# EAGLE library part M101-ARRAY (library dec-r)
M101 Bus Data Interface

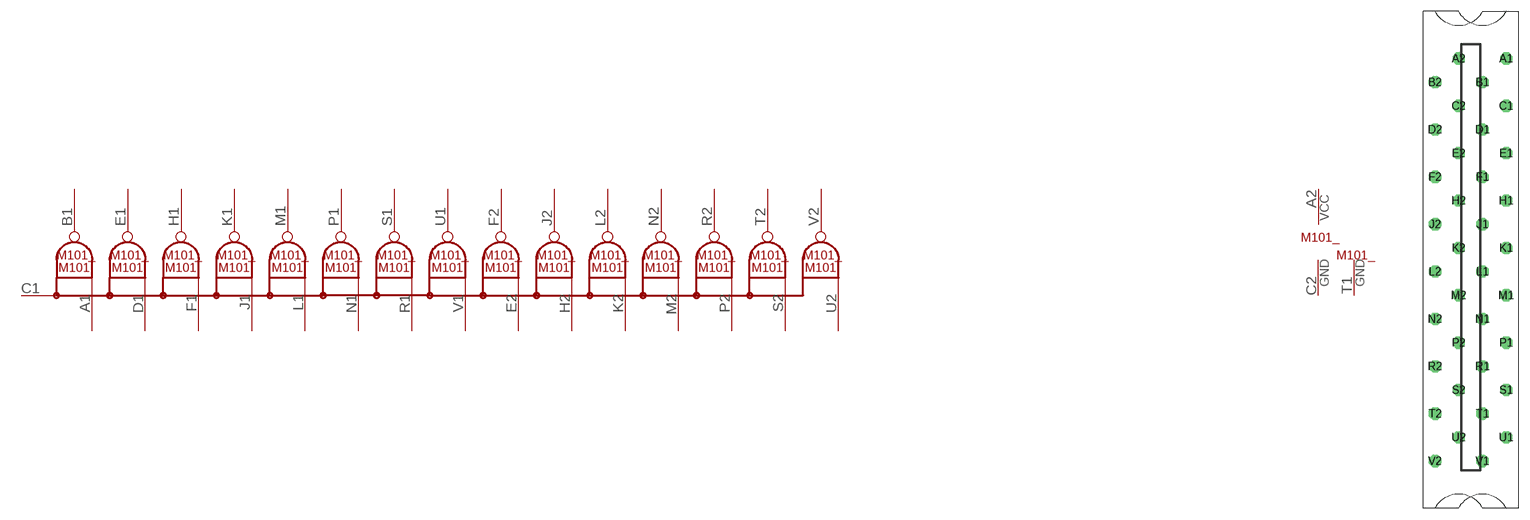
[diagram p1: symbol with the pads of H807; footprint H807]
Designator prefix M101_; gates G$1=M101A G$2=POWER G$3=T1GND

## M101-ARRAY  [H807]
A1  G$1:IN1  in
A2  G$2:VCC  pwr
B1  G$1:O1  out
C1  G$1:ENABLE  in
C2  G$2:GND  pwr
D1  G$1:IN2  in
E1  G$1:O2  out
E2  G$1:IN9  in
F1  G$1:IN3  in
F2  G$1:O9  out
H1  G$1:O3  out
H2  G$1:IN10  in
J1  G$1:IN4  in
J2  G$1:O10  out
K1  G$1:O4  out
K2  G$1:IN11  in
L1  G$1:IN5  in
L2  G$1:O11  out
M1  G$1:O5  out
M2  G$1:IN12  in
N1  G$1:IN6  in
N2  G$1:O12  out
P1  G$1:O6  out
P2  G$1:IN13  in
R1  G$1:IN7  in
R2  G$1:O13  out
S1  G$1:O7  out
S2  G$1:IN14  in
T1  G$3:GND  pwr
T2  G$1:O14  out
U1  G$1:O8  out
U2  G$1:IN15  in
V1  G$1:IN8  in
V2  G$1:O15  out

## Footprint H807 (pad centres in mm)
One-wide female edge connector
drill 1.092 octagon: A1 4.763,28.575; A2 -1.587,28.575; B1 1.587,25.4; B2 -4.763,25.4; C1 4.763,22.225; C2 -1.587,22.225; D1 1.587,19.05; D2 -4.763,19.05; E1 4.763,15.875; E2 -1.587,15.875; F1 1.587,12.7; F2 -4.763,12.7; H1 4.763,9.525; H2 -1.587,9.525; J1 1.587,6.35; J2 -4.763,6.35; K1 4.763,3.175; K2 -1.587,3.175; L1 1.587,0; L2 -4.763,0; M1 4.763,-3.175; M2 -1.587,-3.175; N1 1.587,-6.35; N2 -4.763,-6.35; P1 4.763,-9.525; P2 -1.587,-9.525; R1 1.587,-12.7; R2 -4.763,-12.7; S1 4.763,-15.875; S2 -1.587,-15.875; T1 1.587,-19.05; T2 -4.763,-19.05; U1 4.763,-22.225; U2 -1.587,-22.225; V1 1.587,-25.4; V2 -4.763,-25.4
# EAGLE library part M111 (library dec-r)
Sixteen inverters.

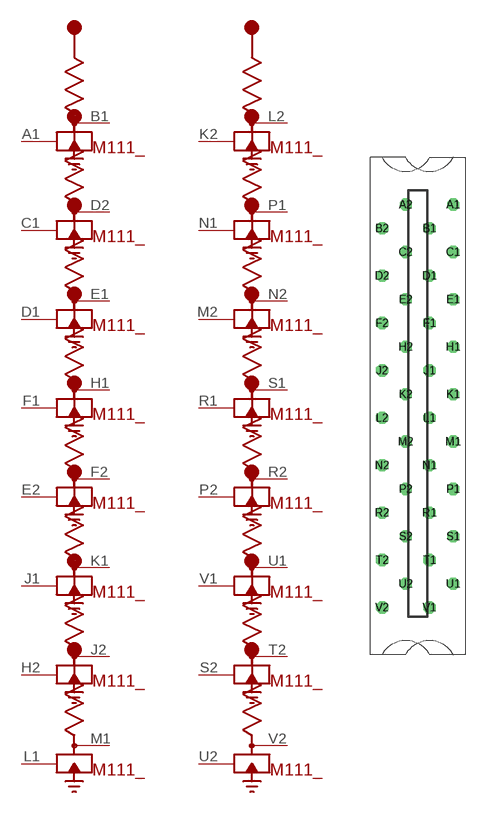
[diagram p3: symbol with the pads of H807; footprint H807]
Designator prefix M111_; gates 3=INVERTER 2=INVERTER 1=INVERTER 13=INVERTER 4=INVERTER 15=INVERTER 14=INVERTER 16=INVERTER 5=INVERTER 6=INVERTER 7=INVERTER 8=INVERTER 9=INVERTER 10=INVERTER 11=INVERTER 12=INVERTER G$17=POWER G$1=T1GND

## M111  [H807]
A1  1:IN  in
A2  G$17:VCC  pwr
B1  1:OUT  out
C1  2:IN  in
C2  G$17:GND  pwr
D1  3:IN  in
D2  2:OUT  out
E1  3:OUT  out
E2  5:IN  in
F1  4:IN  in
F2  5:OUT  out
H1  4:OUT  out
H2  7:IN  in
J1  6:IN  in
J2  7:OUT  out
K1  6:OUT  out
K2  9:IN  in
L1  8:IN  in
L2  9:OUT  out
M1  8:OUT  out
M2  11:IN  in
N1  10:IN  in
N2  11:OUT  out
P1  10:OUT  out
P2  13:IN  in
R1  12:IN  in
R2  13:OUT  out
S1  12:OUT  out
S2  15:IN  in
T1  G$1:GND  pwr
T2  15:OUT  out
U1  14:OUT  out
U2  16:IN  in
V1  14:IN  in
V2  16:OUT  out

## Footprint H807 (pad centres in mm)
One-wide female edge connector
drill 1.092 octagon: A1 4.763,28.575; A2 -1.587,28.575; B1 1.587,25.4; B2 -4.763,25.4; C1 4.763,22.225; C2 -1.587,22.225; D1 1.587,19.05; D2 -4.763,19.05; E1 4.763,15.875; E2 -1.587,15.875; F1 1.587,12.7; F2 -4.763,12.7; H1 4.763,9.525; H2 -1.587,9.525; J1 1.587,6.35; J2 -4.763,6.35; K1 4.763,3.175; K2 -1.587,3.175; L1 1.587,0; L2 -4.763,0; M1 4.763,-3.175; M2 -1.587,-3.175; N1 1.587,-6.35; N2 -4.763,-6.35; P1 4.763,-9.525; P2 -1.587,-9.525; R1 1.587,-12.7; R2 -4.763,-12.7; S1 4.763,-15.875; S2 -1.587,-15.875; T1 1.587,-19.05; T2 -4.763,-19.05; U1 4.763,-22.225; U2 -1.587,-22.225; V1 1.587,-25.4; V2 -4.763,-25.4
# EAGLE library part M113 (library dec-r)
10 2-input NAND Gates

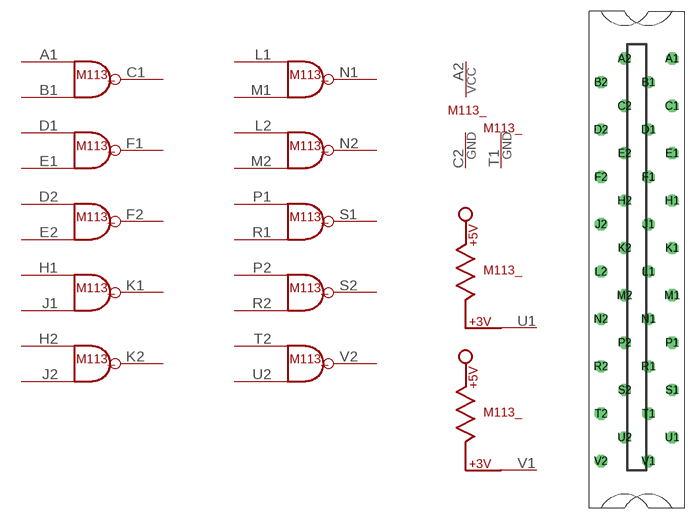
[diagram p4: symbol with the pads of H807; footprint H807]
Designator prefix M113_; gates G$1=NAND2 G$2=NAND2 G$3=NAND2 G$4=NAND2 G$5=NAND2 G$6=NAND2 G$7=NAND2 G$8=NAND2 G$9=NAND2 G$10=NAND2 G$11=POWER G$12=T1GND G$13=PULL-UP G$14=PULL-UP

## M113  [H807]
A1  G$1:IN1  in
A2  G$11:VCC  pwr
B1  G$1:IN2  in
C1  G$1:OUT  out
C2  G$11:GND  pwr
D1  G$2:IN1  in
D2  G$3:IN1  in
E1  G$2:IN2  in
E2  G$3:IN2  in
F1  G$2:OUT  out
F2  G$3:OUT  out
H1  G$4:IN1  in
H2  G$5:IN1  in
J1  G$4:IN2  in
J2  G$5:IN2  in
K1  G$4:OUT  out
K2  G$5:OUT  out
L1  G$6:IN1  in
L2  G$7:IN1  in
M1  G$6:IN2  in
M2  G$7:IN2  in
N1  G$6:OUT  out
N2  G$7:OUT  out
P1  G$8:IN1  in
P2  G$9:IN1  in
R1  G$8:IN2  in
R2  G$9:IN2  in
S1  G$8:OUT  out
S2  G$9:OUT  out
T1  G$12:GND  pwr
T2  G$10:IN1  in
U1  G$13:P$1  pas
U2  G$10:IN2  in
V1  G$14:P$1  pas
V2  G$10:OUT  out

## Footprint H807 (pad centres in mm)
One-wide female edge connector
drill 1.092 octagon: A1 4.763,28.575; A2 -1.587,28.575; B1 1.587,25.4; B2 -4.763,25.4; C1 4.763,22.225; C2 -1.587,22.225; D1 1.587,19.05; D2 -4.763,19.05; E1 4.763,15.875; E2 -1.587,15.875; F1 1.587,12.7; F2 -4.763,12.7; H1 4.763,9.525; H2 -1.587,9.525; J1 1.587,6.35; J2 -4.763,6.35; K1 4.763,3.175; K2 -1.587,3.175; L1 1.587,0; L2 -4.763,0; M1 4.763,-3.175; M2 -1.587,-3.175; N1 1.587,-6.35; N2 -4.763,-6.35; P1 4.763,-9.525; P2 -1.587,-9.525; R1 1.587,-12.7; R2 -4.763,-12.7; S1 4.763,-15.875; S2 -1.587,-15.875; T1 1.587,-19.05; T2 -4.763,-19.05; U1 4.763,-22.225; U2 -1.587,-22.225; V1 1.587,-25.4; V2 -4.763,-25.4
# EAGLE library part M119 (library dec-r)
3 8-input NAND Gates

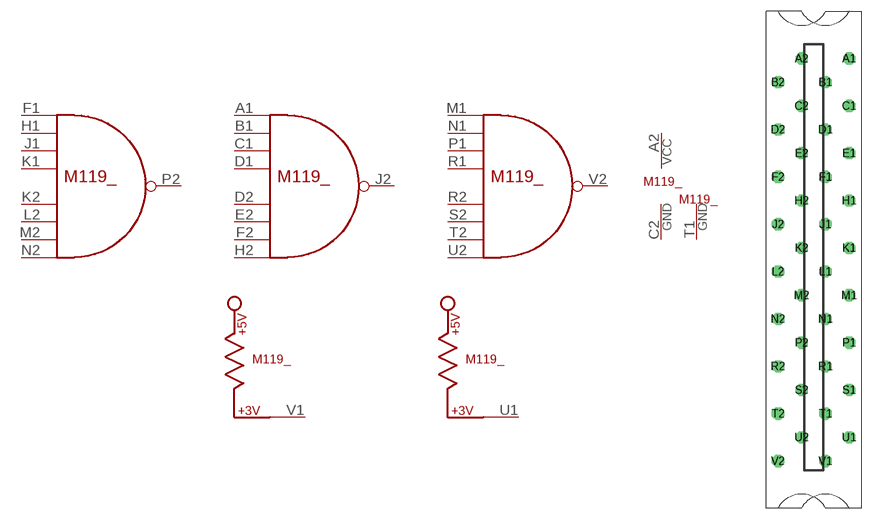
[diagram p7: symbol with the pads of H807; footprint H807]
Designator prefix M119_; gates G$1=NAND8 G$2=NAND8 G$3=NAND8 G$4=POWER G$5=T1GND G$6=PULL-UP G$7=PULL-UP

## M119  [H807]
A1  G$1:IN1  in
A2  G$4:VCC  pwr
B1  G$1:IN2  in
C1  G$1:IN3  in
C2  G$4:GND  pwr
D1  G$1:IN4  in
D2  G$1:IN5  in
E2  G$1:IN6  in
F1  G$2:IN1  in
F2  G$1:IN7  in
H1  G$2:IN2  in
H2  G$1:IN8  in
J1  G$2:IN3  in
J2  G$1:OUT  out
K1  G$2:IN4  in
K2  G$2:IN5  in
L2  G$2:IN6  in
M1  G$3:IN1  in
M2  G$2:IN7  in
N1  G$3:IN2  in
N2  G$2:IN8  in
P1  G$3:IN3  in
P2  G$2:OUT  out
R1  G$3:IN4  in
R2  G$3:IN5  in
S2  G$3:IN6  in
T1  G$5:GND  pwr
T2  G$3:IN7  in
U1  G$6:P$1  pas
U2  G$3:IN8  in
V1  G$7:P$1  pas
V2  G$3:OUT  out

## Footprint H807 (pad centres in mm)
One-wide female edge connector
drill 1.092 octagon: A1 4.763,28.575; A2 -1.587,28.575; B1 1.587,25.4; B2 -4.763,25.4; C1 4.763,22.225; C2 -1.587,22.225; D1 1.587,19.05; D2 -4.763,19.05; E1 4.763,15.875; E2 -1.587,15.875; F1 1.587,12.7; F2 -4.763,12.7; H1 4.763,9.525; H2 -1.587,9.525; J1 1.587,6.35; J2 -4.763,6.35; K1 4.763,3.175; K2 -1.587,3.175; L1 1.587,0; L2 -4.763,0; M1 4.763,-3.175; M2 -1.587,-3.175; N1 1.587,-6.35; N2 -4.763,-6.35; P1 4.763,-9.525; P2 -1.587,-9.525; R1 1.587,-12.7; R2 -4.763,-12.7; S1 4.763,-15.875; S2 -1.587,-15.875; T1 1.587,-19.05; T2 -4.763,-19.05; U1 4.763,-22.225; U2 -1.587,-22.225; V1 1.587,-25.4; V2 -4.763,-25.4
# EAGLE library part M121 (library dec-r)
6 2-2 AND-NOR Gates

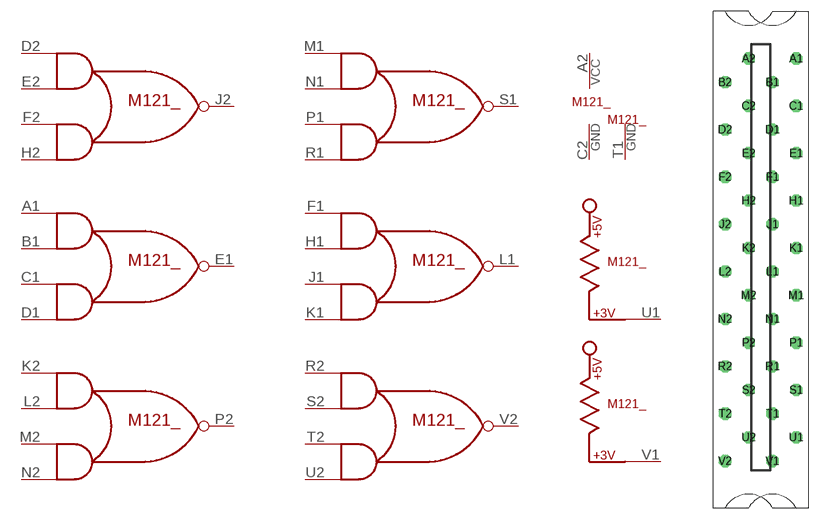
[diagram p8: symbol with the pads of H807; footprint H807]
Designator prefix M121_; gates G$1=AND-NOR G$2=AND-NOR G$3=AND-NOR G$4=AND-NOR G$5=AND-NOR G$6=AND-NOR G$7=POWER G$8=T1GND G$9=PULL-UP G$10=PULL-UP

## M121  [H807]
A1  G$1:IN1A  in
A2  G$7:VCC  pwr
B1  G$1:IN1B  in
C1  G$1:IN2A  in
C2  G$7:GND  pwr
D1  G$1:IN2B  in
D2  G$4:IN1A  in
E1  G$1:OUT  out
E2  G$4:IN1B  in
F1  G$2:IN1A  in
F2  G$4:IN2A  in
H1  G$2:IN1B  in
H2  G$4:IN2B  in
J1  G$2:IN2A  in
J2  G$4:OUT  out
K1  G$2:IN2B  in
K2  G$5:IN1A  in
L1  G$2:OUT  out
L2  G$5:IN1B  in
M1  G$3:IN1A  in
M2  G$5:IN2A  in
N1  G$3:IN1B  in
N2  G$5:IN2B  in
P1  G$3:IN2A  in
P2  G$5:OUT  out
R1  G$3:IN2B  in
R2  G$6:IN1A  in
S1  G$3:OUT  out
S2  G$6:IN1B  in
T1  G$8:GND  pwr
T2  G$6:IN2A  in
U1  G$9:P$1  pas
U2  G$6:IN2B  in
V1  G$10:P$1  pas
V2  G$6:OUT  out

## Footprint H807 (pad centres in mm)
One-wide female edge connector
drill 1.092 octagon: A1 4.763,28.575; A2 -1.587,28.575; B1 1.587,25.4; B2 -4.763,25.4; C1 4.763,22.225; C2 -1.587,22.225; D1 1.587,19.05; D2 -4.763,19.05; E1 4.763,15.875; E2 -1.587,15.875; F1 1.587,12.7; F2 -4.763,12.7; H1 4.763,9.525; H2 -1.587,9.525; J1 1.587,6.35; J2 -4.763,6.35; K1 4.763,3.175; K2 -1.587,3.175; L1 1.587,0; L2 -4.763,0; M1 4.763,-3.175; M2 -1.587,-3.175; N1 1.587,-6.35; N2 -4.763,-6.35; P1 4.763,-9.525; P2 -1.587,-9.525; R1 1.587,-12.7; R2 -4.763,-12.7; S1 4.763,-15.875; S2 -1.587,-15.875; T1 1.587,-19.05; T2 -4.763,-19.05; U1 4.763,-22.225; U2 -1.587,-22.225; V1 1.587,-25.4; V2 -4.763,-25.4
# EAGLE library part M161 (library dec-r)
Octal or Decimal Decoder

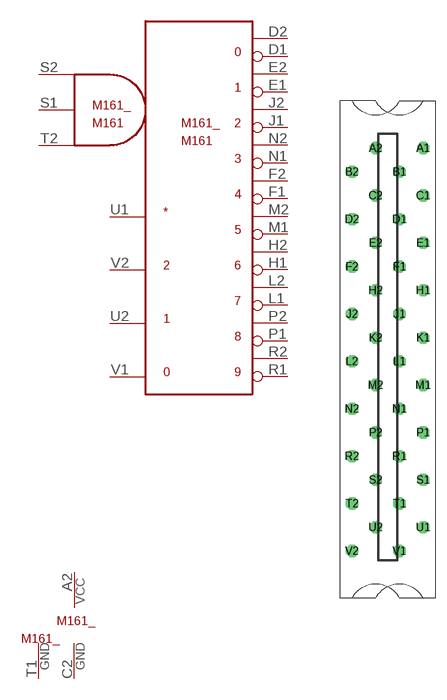
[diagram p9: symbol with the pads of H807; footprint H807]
Designator prefix M161_; gates G$1=M161 G$2=POWER G$3=T1GND

## M161  [H807]
A2  G$2:VCC  pwr
C2  G$2:GND  pwr
D1  G$1:O0\  out
D2  G$1:O0  out
E1  G$1:O1\  out
E2  G$1:O1  out
F1  G$1:O4\  out
F2  G$1:O4  out
H1  G$1:O6\  out
H2  G$1:O6  out
J1  G$1:O2\  out
J2  G$1:O2  out
L1  G$1:O7\  out
L2  G$1:O7  out
M1  G$1:O5\  out
M2  G$1:O5  out
N1  G$1:O3\  out
N2  G$1:O3  out
P1  G$1:O8\  out
P2  G$1:O8  out
R1  G$1:O9\  out
R2  G$1:O9  out
S1  G$1:EN2  in
S2  G$1:EN1  in
T1  G$3:GND  pwr
T2  G$1:EN3  in
U1  G$1:IN*  in
U2  G$1:IN1  in
V1  G$1:IN0  in
V2  G$1:IN2  in

## Footprint H807 (pad centres in mm)
One-wide female edge connector
drill 1.092 octagon: A1 4.763,28.575; A2 -1.587,28.575; B1 1.587,25.4; B2 -4.763,25.4; C1 4.763,22.225; C2 -1.587,22.225; D1 1.587,19.05; D2 -4.763,19.05; E1 4.763,15.875; E2 -1.587,15.875; F1 1.587,12.7; F2 -4.763,12.7; H1 4.763,9.525; H2 -1.587,9.525; J1 1.587,6.35; J2 -4.763,6.35; K1 4.763,3.175; K2 -1.587,3.175; L1 1.587,0; L2 -4.763,0; M1 4.763,-3.175; M2 -1.587,-3.175; N1 1.587,-6.35; N2 -4.763,-6.35; P1 4.763,-9.525; P2 -1.587,-9.525; R1 1.587,-12.7; R2 -4.763,-12.7; S1 4.763,-15.875; S2 -1.587,-15.875; T1 1.587,-19.05; T2 -4.763,-19.05; U1 4.763,-22.225; U2 -1.587,-22.225; V1 1.587,-25.4; V2 -4.763,-25.4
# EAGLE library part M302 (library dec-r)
Dual one-shot

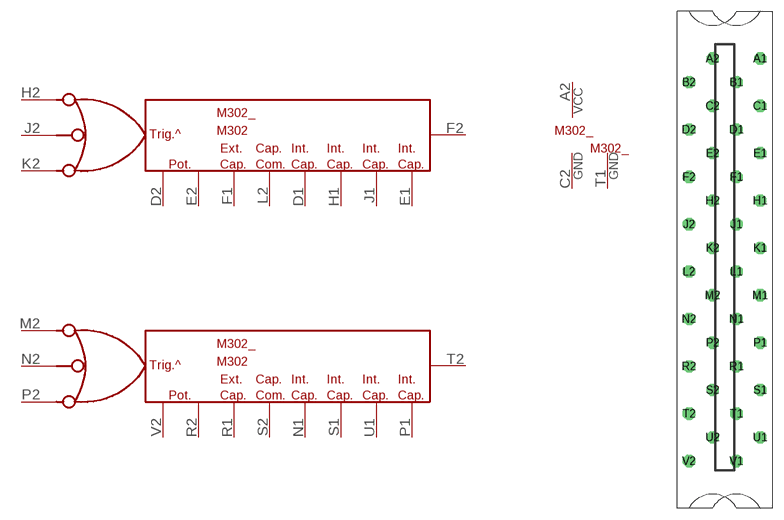
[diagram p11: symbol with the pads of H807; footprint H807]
Designator prefix M302_; gates G$1=M302A G$2=M302A G$3=POWER G$4=T1GND

## M302  [H807]
A2  G$3:VCC  pwr
C2  G$3:GND  pwr
D1  G$1:D1  pas
D2  G$1:D2  pas
E1  G$1:E1  pas
E2  G$1:E2  pas
F1  G$1:F1  pas
F2  G$1:F2  out
H1  G$1:H1  pas
H2  G$1:H2  in
J1  G$1:J1  pas
J2  G$1:J2  in
K2  G$1:K2  in
L2  G$1:L2  pas
M2  G$2:H2  in
N1  G$2:D1  pas
N2  G$2:J2  in
P1  G$2:E1  pas
P2  G$2:K2  in
R1  G$2:F1  pas
R2  G$2:E2  pas
S1  G$2:H1  pas
S2  G$2:L2  pas
T1  G$4:GND  pwr
T2  G$2:F2  out
U1  G$2:J1  pas
V2  G$2:D2  pas

## Footprint H807 (pad centres in mm)
One-wide female edge connector
drill 1.092 octagon: A1 4.763,28.575; A2 -1.587,28.575; B1 1.587,25.4; B2 -4.763,25.4; C1 4.763,22.225; C2 -1.587,22.225; D1 1.587,19.05; D2 -4.763,19.05; E1 4.763,15.875; E2 -1.587,15.875; F1 1.587,12.7; F2 -4.763,12.7; H1 4.763,9.525; H2 -1.587,9.525; J1 1.587,6.35; J2 -4.763,6.35; K1 4.763,3.175; K2 -1.587,3.175; L1 1.587,0; L2 -4.763,0; M1 4.763,-3.175; M2 -1.587,-3.175; N1 1.587,-6.35; N2 -4.763,-6.35; P1 4.763,-9.525; P2 -1.587,-9.525; R1 1.587,-12.7; R2 -4.763,-12.7; S1 4.763,-15.875; S2 -1.587,-15.875; T1 1.587,-19.05; T2 -4.763,-19.05; U1 4.763,-22.225; U2 -1.587,-22.225; V1 1.587,-25.4; V2 -4.763,-25.4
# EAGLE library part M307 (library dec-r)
Dual Integrating One-Shot

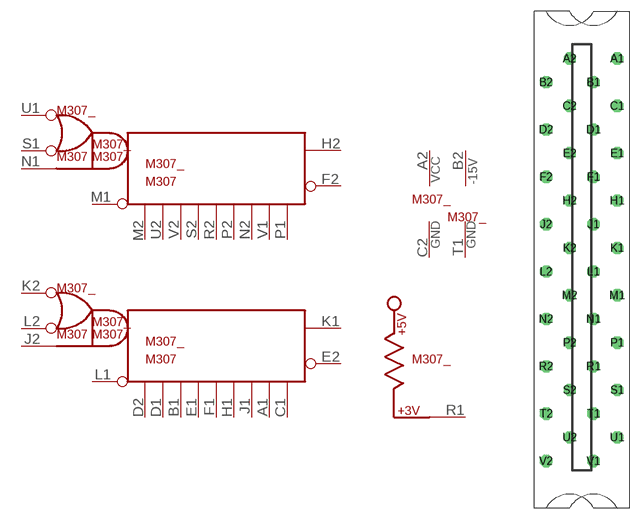
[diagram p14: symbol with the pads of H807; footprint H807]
Designator prefix M307_; gates G$1=M307A G$2=M307A G$3=POWER G$4=T1GND G$5=-15V G$6=PULL-UP

## M307  [H807]
A1  G$2:V1  pas
A2  G$3:VCC  pwr
B1  G$2:V2  pas
B2  G$5:-15V  pwr
C1  G$2:P1  pas
C2  G$3:GND  pwr
D1  G$2:U2  pas
D2  G$2:M2  pas
E1  G$2:S2  pas
E2  G$2:F2  out
F1  G$2:R2  pas
F2  G$1:F2  out
H1  G$2:P2  pas
H2  G$1:H2  out
J1  G$2:N2  pas
J2  G$2:N1  in
K1  G$2:H2  out
K2  G$2:U1  in
L1  G$2:M1  in
L2  G$2:S1  in
M1  G$1:M1  in
M2  G$1:M2  pas
N1  G$1:N1  in
N2  G$1:N2  pas
P1  G$1:P1  pas
P2  G$1:P2  pas
R1  G$6:P$1  pas
R2  G$1:R2  pas
S1  G$1:S1  in
S2  G$1:S2  pas
T1  G$4:GND  pwr
U1  G$1:U1  in
U2  G$1:U2  pas
V1  G$1:V1  pas
V2  G$1:V2  pas

## Footprint H807 (pad centres in mm)
One-wide female edge connector
drill 1.092 octagon: A1 4.763,28.575; A2 -1.587,28.575; B1 1.587,25.4; B2 -4.763,25.4; C1 4.763,22.225; C2 -1.587,22.225; D1 1.587,19.05; D2 -4.763,19.05; E1 4.763,15.875; E2 -1.587,15.875; F1 1.587,12.7; F2 -4.763,12.7; H1 4.763,9.525; H2 -1.587,9.525; J1 1.587,6.35; J2 -4.763,6.35; K1 4.763,3.175; K2 -1.587,3.175; L1 1.587,0; L2 -4.763,0; M1 4.763,-3.175; M2 -1.587,-3.175; N1 1.587,-6.35; N2 -4.763,-6.35; P1 4.763,-9.525; P2 -1.587,-9.525; R1 1.587,-12.7; R2 -4.763,-12.7; S1 4.763,-15.875; S2 -1.587,-15.875; T1 1.587,-19.05; T2 -4.763,-19.05; U1 4.763,-22.225; U2 -1.587,-22.225; V1 1.587,-25.4; V2 -4.763,-25.4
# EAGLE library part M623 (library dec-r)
6 Dual Bus Drivers

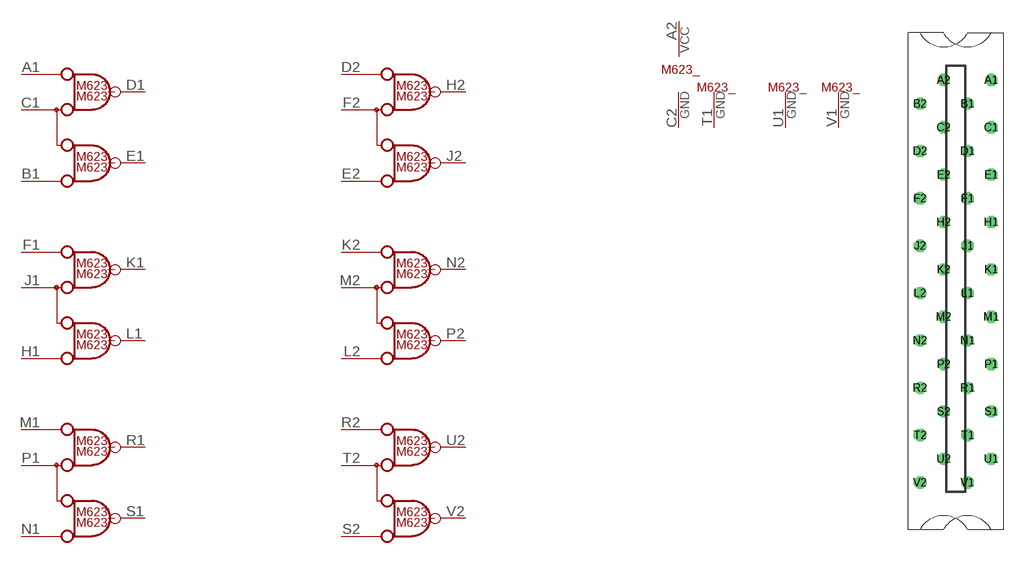
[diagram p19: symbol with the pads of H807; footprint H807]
Designator prefix M623_; gates G$1=M623A G$2=M623A G$3=M623A G$4=M623A G$5=M623A G$6=M623A G$7=POWER G$8=T1GND G$9=T1GND G$10=T1GND

## M623  [H807]
A1  G$1:A  in
A2  G$7:VCC  pwr
B1  G$1:B  in
C1  G$1:C  in
C2  G$7:GND  pwr
D1  G$1:D  oc
D2  G$4:A  in
E1  G$1:E  oc
E2  G$4:B  in
F1  G$2:A  in
F2  G$4:C  in
H1  G$2:B  in
H2  G$4:D  oc
J1  G$2:C  in
J2  G$4:E  oc
K1  G$2:D  oc
K2  G$5:A  in
L1  G$2:E  oc
L2  G$5:B  in
M1  G$3:A  in
M2  G$5:C  in
N1  G$3:B  in
N2  G$5:D  oc
P1  G$3:C  in
P2  G$5:E  oc
R1  G$3:D  oc
R2  G$6:A  in
S1  G$3:E  oc
S2  G$6:B  in
T1  G$8:GND  pwr
T2  G$6:C  in
U1  G$9:GND  pwr
U2  G$6:D  oc
V1  G$10:GND  pwr
V2  G$6:E  oc

## Footprint H807 (pad centres in mm)
One-wide female edge connector
drill 1.092 octagon: A1 4.763,28.575; A2 -1.587,28.575; B1 1.587,25.4; B2 -4.763,25.4; C1 4.763,22.225; C2 -1.587,22.225; D1 1.587,19.05; D2 -4.763,19.05; E1 4.763,15.875; E2 -1.587,15.875; F1 1.587,12.7; F2 -4.763,12.7; H1 4.763,9.525; H2 -1.587,9.525; J1 1.587,6.35; J2 -4.763,6.35; K1 4.763,3.175; K2 -1.587,3.175; L1 1.587,0; L2 -4.763,0; M1 4.763,-3.175; M2 -1.587,-3.175; N1 1.587,-6.35; N2 -4.763,-6.35; P1 4.763,-9.525; P2 -1.587,-9.525; R1 1.587,-12.7; R2 -4.763,-12.7; S1 4.763,-15.875; S2 -1.587,-15.875; T1 1.587,-19.05; T2 -4.763,-19.05; U1 4.763,-22.225; U2 -1.587,-22.225; V1 1.587,-25.4; V2 -4.763,-25.4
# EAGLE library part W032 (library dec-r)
Cable Connector (15 signals)

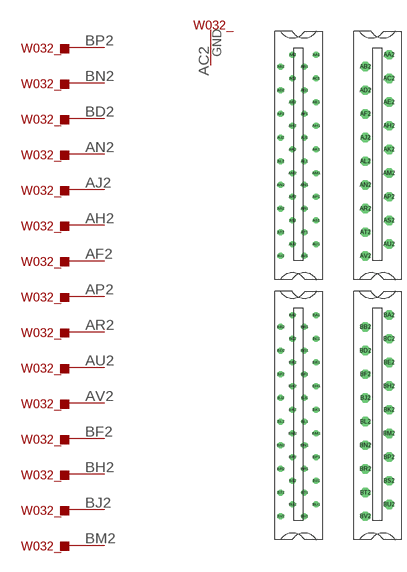
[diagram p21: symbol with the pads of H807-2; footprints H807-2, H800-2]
Designator prefix W032_; gates AF=PIN AH=PIN AJ=PIN AN=PIN AP=PIN AR=PIN AU=PIN AV=PIN BD=PIN BF=PIN BH=PIN BJ=PIN BM=PIN BN=PIN BP=PIN G$16=T1GND G$17=T1GND G$18=T1GND G$19=T1GND G$20=T1GND G$21=T1GND

## W032  [H807-2]
AC2  G$16:GND  pwr
AF2  AF:P$2
AH2  AH:P$2
AJ2  AJ:P$2
AK2  G$17:GND  pwr
AN2  AN:P$2
AP2  AP:P$2
AR2  AR:P$2
AS2  G$18:GND  pwr
AT2  G$19:GND  pwr
AU2  AU:P$2
AV2  AV:P$2
BD2  BD:P$2
BE2  G$20:GND  pwr
BF2  BF:P$2
BH2  BH:P$2
BJ2  BJ:P$2
BL2  G$21:GND  pwr
BM2  BM:P$2
BN2  BN:P$2
BP2  BP:P$2

## W032O  [H800-2]
Pads as for H807-2

## W032S  [H807S-2]
Pads as for H807-2

## Footprint H807-2 (pad centres in mm)
Two-wide Female Edge Connector
drill 1.092 octagon: AA1 4.763,60.325; AA2 -1.587,60.325; AB1 1.587,57.15; AB2 -4.763,57.15; AC1 4.763,53.975; AC2 -1.587,53.975; AD1 1.587,50.8; AD2 -4.763,50.8; AE1 4.763,47.625; AE2 -1.587,47.625; AF1 1.587,44.45; AF2 -4.763,44.45; AH1 4.763,41.275; AH2 -1.587,41.275; AJ1 1.587,38.1; AJ2 -4.763,38.1; AK1 4.763,34.925; AK2 -1.587,34.925; AL1 1.587,31.75; AL2 -4.763,31.75; AM1 4.763,28.575; AM2 -1.587,28.575; AN1 1.587,25.4; AN2 -4.763,25.4; AP1 4.763,22.225; AP2 -1.587,22.225; AR1 1.587,19.05; AR2 -4.763,19.05; AS1 4.763,15.875; AS2 -1.587,15.875; AT1 1.587,12.7; AT2 -4.763,12.7; AU1 4.763,9.525; AU2 -1.587,9.525; AV1 1.587,6.35; AV2 -4.763,6.35; BA1 4.763,-9.525; BA2 -1.587,-9.525; BB1 1.587,-12.7; BB2 -4.763,-12.7; BC1 4.763,-15.875; BC2 -1.587,-15.875; BD1 1.587,-19.05; BD2 -4.763,-19.05; BE1 4.763,-22.225; BE2 -1.587,-22.225; BF1 1.587,-25.4; BF2 -4.763,-25.4; BH1 4.763,-28.575; BH2 -1.587,-28.575; BJ1 1.587,-31.75; BJ2 -4.763,-31.75; BK1 4.763,-34.925; BK2 -1.587,-34.925; BL1 1.587,-38.1; BL2 -4.763,-38.1; BM1 4.763,-41.275; BM2 -1.587,-41.275; BN1 1.587,-44.45; BN2 -4.763,-44.45; BP1 4.763,-47.625; BP2 -1.587,-47.625; BR1 1.587,-50.8; BR2 -4.763,-50.8; BS1 4.763,-53.975; BS2 -1.587,-53.975; BT1 1.587,-57.15; BT2 -4.763,-57.15; BU1 4.763,-60.325; BU2 -1.587,-60.325; BV1 1.587,-63.5; BV2 -4.763,-63.5

## Footprint H800-2 (pad centres in mm)
Two-wide Female Edge Connector
drill 1.676 octagon: AA2 3.175,60.325; AB2 -3.175,57.15; AC2 3.175,53.975; AD2 -3.175,50.8; AE2 3.175,47.625; AF2 -3.175,44.45; AH2 3.175,41.275; AJ2 -3.175,38.1; AK2 3.175,34.925; AL2 -3.175,31.75; AM2 3.175,28.575; AN2 -3.175,25.4; AP2 3.175,22.225; AR2 -3.175,19.05; AS2 3.175,15.875; AT2 -3.175,12.7; AU2 3.175,9.525; AV2 -3.175,6.35; BA2 3.175,-9.525; BB2 -3.175,-12.7; BC2 3.175,-15.875; BD2 -3.175,-19.05; BE2 3.175,-22.225; BF2 -3.175,-25.4; BH2 3.175,-28.575; BJ2 -3.175,-31.75; BK2 3.175,-34.925; BL2 -3.175,-38.1; BM2 3.175,-41.275; BN2 -3.175,-44.45; BP2 3.175,-47.625; BR2 -3.175,-50.8; BS2 3.175,-53.975; BT2 -3.175,-57.15; BU2 3.175,-60.325; BV2 -3.175,-63.5

## Footprint H807S-2 (pad centres in mm)
Two-wide Female Edge Connector, Side 2 only
drill 1.092 octagon: AA2 -1.587,60.325; AB2 -4.763,57.15; AC2 -1.587,53.975; AD2 -4.763,50.8; AE2 -1.587,47.625; AF2 -4.763,44.45; AH2 -1.587,41.275; AJ2 -4.763,38.1; AK2 -1.587,34.925; AL2 -4.763,31.75; AM2 -1.587,28.575; AN2 -4.763,25.4; AP2 -1.587,22.225; AR2 -4.763,19.05; AS2 -1.587,15.875; AT2 -4.763,12.7; AU2 -1.587,9.525; AV2 -4.763,6.35; BA2 -1.587,-9.525; BB2 -4.763,-12.7; BC2 -1.587,-15.875; BD2 -4.763,-19.05; BE2 -1.587,-22.225; BF2 -4.763,-25.4; BH2 -1.587,-28.575; BJ2 -4.763,-31.75; BK2 -1.587,-34.925; BL2 -4.763,-38.1; BM2 -1.587,-41.275; BN2 -4.763,-44.45; BP2 -1.587,-47.625; BR2 -4.763,-50.8; BS2 -1.587,-53.975; BT2 -4.763,-57.15; BU2 -1.587,-60.325; BV2 -4.763,-63.5
hole 1.092 at 4.763,60.325
hole 1.092 at 1.587,57.15
hole 1.092 at 4.763,53.975
hole 1.092 at 1.587,50.8
hole 1.092 at 4.763,47.625
hole 1.092 at 1.587,44.45
hole 1.092 at 4.763,41.275
hole 1.092 at 1.587,38.1
hole 1.092 at 4.763,34.925
hole 1.092 at 1.587,31.75
hole 1.092 at 4.763,28.575
hole 1.092 at 4.763,-9.525
hole 1.092 at 1.587,-12.7
hole 1.092 at 4.763,-15.875
hole 1.092 at 1.587,-19.05
hole 1.092 at 4.763,-22.225
hole 1.092 at 1.587,-25.4
hole 1.092 at 4.763,-28.575
hole 1.092 at 1.587,-31.75
hole 1.092 at 4.763,-34.925
hole 1.092 at 1.587,-38.1
hole 1.092 at 4.763,-41.275
hole 1.092 at 1.587,-44.45
hole 1.092 at 4.763,-47.625
hole 1.092 at 1.587,-50.8
hole 1.092 at 4.763,-53.975
hole 1.092 at 1.587,-57.15
hole 1.092 at 4.763,-60.325
hole 1.092 at 1.587,-63.5
hole 1.092 at 1.587,25.4
hole 1.092 at 4.763,22.225
hole 1.092 at 1.587,19.05
hole 1.092 at 4.763,15.875
hole 1.092 at 1.587,12.7
hole 1.092 at 4.763,9.525
hole 1.092 at 1.587,6.35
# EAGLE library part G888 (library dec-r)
Manchester Reader/Writer

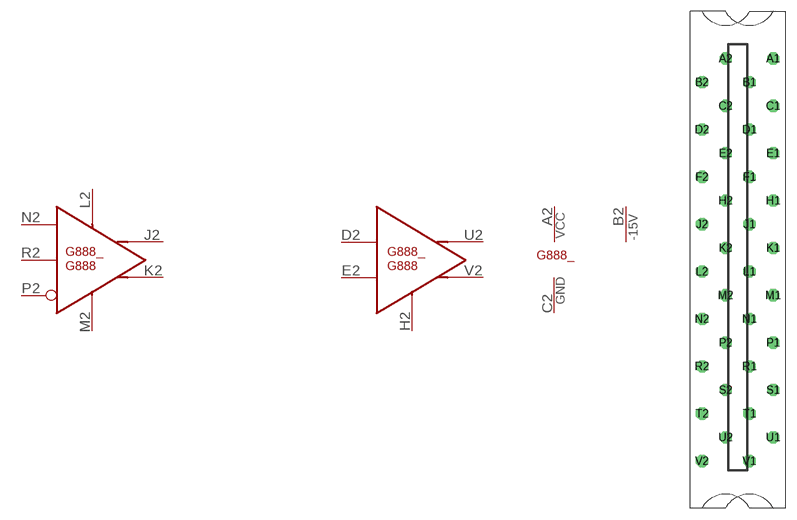
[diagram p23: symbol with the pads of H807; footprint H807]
Designator prefix G888_; gates G$1=G888 G$2=POWER G$3=-15V

## G888  [H807]
A2  G$2:VCC  pwr
B2  G$3:-15V  pwr
C2  G$2:GND  pwr
D2  G$1:D2  in
E2  G$1:E2  in
H2  G$1:H2  in
J2  G$1:J2  out
K2  G$1:K2  out
L2  G$1:L2  in
M2  G$1:M2  in
N2  G$1:N2  in
P2  G$1:P2  in
R2  G$1:R2  in
U2  G$1:U2  out
V2  G$1:V2  out

## Footprint H807 (pad centres in mm)
One-wide female edge connector
drill 1.092 octagon: A1 4.763,28.575; A2 -1.587,28.575; B1 1.587,25.4; B2 -4.763,25.4; C1 4.763,22.225; C2 -1.587,22.225; D1 1.587,19.05; D2 -4.763,19.05; E1 4.763,15.875; E2 -1.587,15.875; F1 1.587,12.7; F2 -4.763,12.7; H1 4.763,9.525; H2 -1.587,9.525; J1 1.587,6.35; J2 -4.763,6.35; K1 4.763,3.175; K2 -1.587,3.175; L1 1.587,0; L2 -4.763,0; M1 4.763,-3.175; M2 -1.587,-3.175; N1 1.587,-6.35; N2 -4.763,-6.35; P1 4.763,-9.525; P2 -1.587,-9.525; R1 1.587,-12.7; R2 -4.763,-12.7; S1 4.763,-15.875; S2 -1.587,-15.875; T1 1.587,-19.05; T2 -4.763,-19.05; U1 4.763,-22.225; U2 -1.587,-22.225; V1 1.587,-25.4; V2 -4.763,-25.4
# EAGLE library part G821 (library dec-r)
+5V Regulator

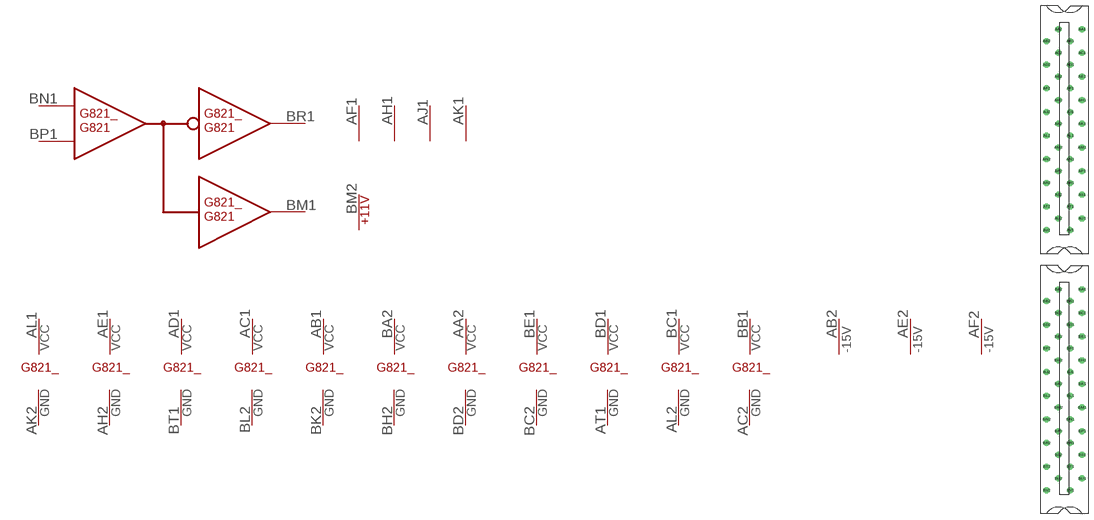
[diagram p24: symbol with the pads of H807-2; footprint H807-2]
Designator prefix G821_; gates G$1=-15V G$2=POWER G$3=-15V G$4=-15V G$5=POWER G$6=POWER G$7=POWER G$8=POWER G$9=POWER G$10=POWER G$11=POWER G$12=POWER G$13=POWER G$15=POWER G$14=G821A

## G821  [H807-2]
AA2  G$8:VCC  pwr
AB1  G$10:VCC  pwr
AB2  G$1:-15V  pwr
AC1  G$11:VCC  pwr
AC2  G$2:GND  pwr
AD1  G$12:VCC  pwr
AE1  G$13:VCC  pwr
AE2  G$4:-15V  pwr
AF1  G$14:VCC  sup
AF2  G$3:-15V  pwr
AH1  G$14:VCC  sup
AH2  G$13:GND  pwr
AJ1  G$14:VCC  sup
AK1  G$14:VCC  sup
AK2  G$15:GND  pwr
AL1  G$15:VCC  pwr
AL2  G$5:GND  pwr
AT1  G$6:GND  pwr
BA2  G$9:VCC  pwr
BB1  G$2:VCC  pwr
BC1  G$5:VCC  pwr
BC2  G$7:GND  pwr
BD1  G$6:VCC  pwr
BD2  G$8:GND  pwr
BE1  G$7:VCC  pwr
BH2  G$9:GND  pwr
BK2  G$10:GND  pwr
BL2  G$11:GND  pwr
BM1  G$14:BM1  out
BM2  G$14:+11V  pwr
BN1  G$14:BN1  in
BP1  G$14:BP1  in
BR1  G$14:BR1  out
BT1  G$12:GND  pwr

## Footprint H807-2 (pad centres in mm)
Two-wide Female Edge Connector
drill 1.092 octagon: AA1 4.763,60.325; AA2 -1.587,60.325; AB1 1.587,57.15; AB2 -4.763,57.15; AC1 4.763,53.975; AC2 -1.587,53.975; AD1 1.587,50.8; AD2 -4.763,50.8; AE1 4.763,47.625; AE2 -1.587,47.625; AF1 1.587,44.45; AF2 -4.763,44.45; AH1 4.763,41.275; AH2 -1.587,41.275; AJ1 1.587,38.1; AJ2 -4.763,38.1; AK1 4.763,34.925; AK2 -1.587,34.925; AL1 1.587,31.75; AL2 -4.763,31.75; AM1 4.763,28.575; AM2 -1.587,28.575; AN1 1.587,25.4; AN2 -4.763,25.4; AP1 4.763,22.225; AP2 -1.587,22.225; AR1 1.587,19.05; AR2 -4.763,19.05; AS1 4.763,15.875; AS2 -1.587,15.875; AT1 1.587,12.7; AT2 -4.763,12.7; AU1 4.763,9.525; AU2 -1.587,9.525; AV1 1.587,6.35; AV2 -4.763,6.35; BA1 4.763,-9.525; BA2 -1.587,-9.525; BB1 1.587,-12.7; BB2 -4.763,-12.7; BC1 4.763,-15.875; BC2 -1.587,-15.875; BD1 1.587,-19.05; BD2 -4.763,-19.05; BE1 4.763,-22.225; BE2 -1.587,-22.225; BF1 1.587,-25.4; BF2 -4.763,-25.4; BH1 4.763,-28.575; BH2 -1.587,-28.575; BJ1 1.587,-31.75; BJ2 -4.763,-31.75; BK1 4.763,-34.925; BK2 -1.587,-34.925; BL1 1.587,-38.1; BL2 -4.763,-38.1; BM1 4.763,-41.275; BM2 -1.587,-41.275; BN1 1.587,-44.45; BN2 -4.763,-44.45; BP1 4.763,-47.625; BP2 -1.587,-47.625; BR1 1.587,-50.8; BR2 -4.763,-50.8; BS1 4.763,-53.975; BS2 -1.587,-53.975; BT1 1.587,-57.15; BT2 -4.763,-57.15; BU1 4.763,-60.325; BU2 -1.587,-60.325; BV1 1.587,-63.5; BV2 -4.763,-63.5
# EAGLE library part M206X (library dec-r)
Two sets of 3 D flip-flops

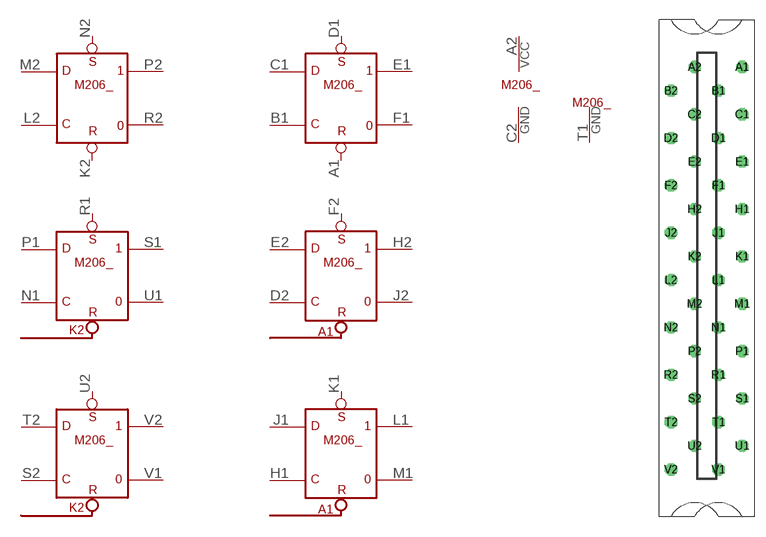
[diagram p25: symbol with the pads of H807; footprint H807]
Designator prefix M206_; gates K2=D-FLOP A1=D-FLOP G$7=POWER G$8=T1GND K2B=D-FLOP-K2 K2C=D-FLOP-K2 A1B=D-FLOP-A1 A1C=D-FLOP-A1

## M206X  [H807]
A1  A1:R  in
A2  G$7:VCC  pwr
B1  A1:C  in
C1  A1:D  in
C2  G$7:GND  pwr
D1  A1:S  in
D2  A1B:C  in
E1  A1:1  out
E2  A1B:D  in
F1  A1:0  out
F2  A1B:S  in
H1  A1C:C  in
H2  A1B:1  out
J1  A1C:D  in
J2  A1B:0  out
K1  A1C:S  in
K2  K2:R  in
L1  A1C:1  out
L2  K2:C  in
M1  A1C:0  out
M2  K2:D  in
N1  K2B:C  in
N2  K2:S  in
P1  K2B:D  in
P2  K2:1  out
R1  K2B:S  in
R2  K2:0  out
S1  K2B:1  out
S2  K2C:C  in
T1  G$8:GND  pwr
T2  K2C:D  in
U1  K2B:0  out
U2  K2C:S  in
V1  K2C:0  out
V2  K2C:1  out

## Footprint H807 (pad centres in mm)
One-wide female edge connector
drill 1.092 octagon: A1 4.763,28.575; A2 -1.587,28.575; B1 1.587,25.4; B2 -4.763,25.4; C1 4.763,22.225; C2 -1.587,22.225; D1 1.587,19.05; D2 -4.763,19.05; E1 4.763,15.875; E2 -1.587,15.875; F1 1.587,12.7; F2 -4.763,12.7; H1 4.763,9.525; H2 -1.587,9.525; J1 1.587,6.35; J2 -4.763,6.35; K1 4.763,3.175; K2 -1.587,3.175; L1 1.587,0; L2 -4.763,0; M1 4.763,-3.175; M2 -1.587,-3.175; N1 1.587,-6.35; N2 -4.763,-6.35; P1 4.763,-9.525; P2 -1.587,-9.525; R1 1.587,-12.7; R2 -4.763,-12.7; S1 4.763,-15.875; S2 -1.587,-15.875; T1 1.587,-19.05; T2 -4.763,-19.05; U1 4.763,-22.225; U2 -1.587,-22.225; V1 1.587,-25.4; V2 -4.763,-25.4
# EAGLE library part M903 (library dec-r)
Two-sided Posibus cable/connector.

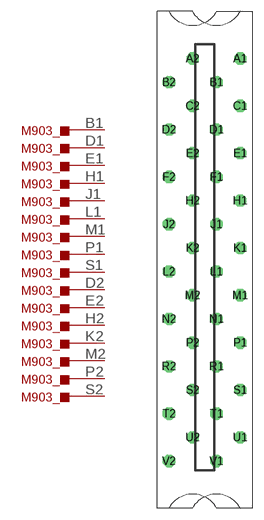
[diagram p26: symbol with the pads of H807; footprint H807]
Designator prefix M903_; gates G$1=PIN G$2=PIN G$3=PIN G$4=PIN G$5=PIN G$6=PIN G$7=PIN G$8=PIN G$9=PIN G$10=PIN G$11=PIN G$12=PIN G$13=PIN G$14=PIN G$15=PIN G$16=PIN G$17=PIN G$18=PIN G$19=T1GND G$20=T1GND G$21=T1GND G$22=T1GND G$23=T1GND G$24=T1GND G$25=T1GND G$26=T1GND G$27=T1GND G$28=T1GND G$29=T1GND G$30=T1GND G$31=T1GND G$32=T1GND

## M903  [H807]
A1  G$19:GND  pwr
B1  G$1:P$2
C1  G$20:GND  pwr
C2  G$26:GND  pwr
D1  G$2:P$2
D2  G$10:P$2
E1  G$3:P$2
E2  G$11:P$2
F1  G$21:GND  pwr
F2  G$27:GND  pwr
H1  G$4:P$2
H2  G$12:P$2
J1  G$5:P$2
J2  G$28:GND  pwr
K1  G$22:GND  pwr
K2  G$13:P$2
L1  G$6:P$2
L2  G$29:GND  pwr
M1  G$7:P$2
M2  G$14:P$2
N1  G$23:GND  pwr
N2  G$30:GND  pwr
P1  G$8:P$2
P2  G$15:P$2
R1  G$24:GND  pwr
R2  G$31:GND  pwr
S1  G$9:P$2
S2  G$16:P$2
T1  G$25:GND  pwr
T2  G$17:P$2
U2  G$32:GND  pwr
V2  G$18:P$2

## Footprint H807 (pad centres in mm)
One-wide female edge connector
drill 1.092 octagon: A1 4.763,28.575; A2 -1.587,28.575; B1 1.587,25.4; B2 -4.763,25.4; C1 4.763,22.225; C2 -1.587,22.225; D1 1.587,19.05; D2 -4.763,19.05; E1 4.763,15.875; E2 -1.587,15.875; F1 1.587,12.7; F2 -4.763,12.7; H1 4.763,9.525; H2 -1.587,9.525; J1 1.587,6.35; J2 -4.763,6.35; K1 4.763,3.175; K2 -1.587,3.175; L1 1.587,0; L2 -4.763,0; M1 4.763,-3.175; M2 -1.587,-3.175; N1 1.587,-6.35; N2 -4.763,-6.35; P1 4.763,-9.525; P2 -1.587,-9.525; R1 1.587,-12.7; R2 -4.763,-12.7; S1 4.763,-15.875; S2 -1.587,-15.875; T1 1.587,-19.05; T2 -4.763,-19.05; U1 4.763,-22.225; U2 -1.587,-22.225; V1 1.587,-25.4; V2 -4.763,-25.4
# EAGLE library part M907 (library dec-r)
M907 Diode Clamp

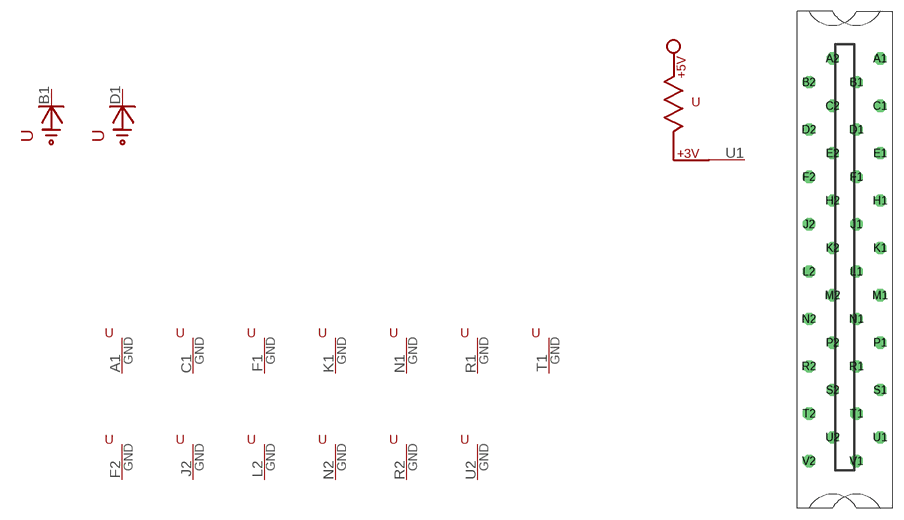
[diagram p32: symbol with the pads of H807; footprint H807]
Designator prefix -; gates G$10=T1GND G$11=T1GND G$12=T1GND G$13=T1GND G$14=T1GND G$15=T1GND G$16=T1GND G$17=PULL-UP G$27=T1GND G$29=T1GND G$30=T1GND G$31=T1GND G$32=T1GND G$33=T1GND G$1=DIODECLAMP G$2=DIODECLAMP G$3=DIODECLAMP G$4=DIODECLAMP G$5=DIODECLAMP G$6=DIODECLAMP G$7=DIODECLAMP G$8=DIODECLAMP G$9=DIODECLAMP G$18=DIODECLAMP G$19=DIODECLAMP G$20=DIODECLAMP G$21=DIODECLAMP G$22=DIODECLAMP G$23=DIODECLAMP G$24=DIODECLAMP G$25=DIODECLAMP G$26=DIODECLAMP G$34=PULL-UP G$35=POWER

## M907  [H807]
A1  G$10:GND  pwr
A2  G$35:VCC  pwr
B1  G$1:CATHODE  pas
C1  G$11:GND  pwr
C2  G$35:GND  pwr
D1  G$2:CATHODE  pas
D2  G$18:CATHODE  pas
E1  G$3:CATHODE  pas
E2  G$19:CATHODE  pas
F1  G$12:GND  pwr
F2  G$29:GND  pwr
H1  G$4:CATHODE  pas
H2  G$20:CATHODE  pas
J1  G$5:CATHODE  pas
J2  G$30:GND  pwr
K1  G$13:GND  pwr
K2  G$21:CATHODE  pas
L1  G$6:CATHODE  pas
L2  G$31:GND  pwr
M1  G$7:CATHODE  pas
M2  G$22:CATHODE  pas
N1  G$14:GND  pwr
N2  G$32:GND  pwr
P1  G$8:CATHODE  pas
P2  G$23:CATHODE  pas
R1  G$15:GND  pwr
R2  G$33:GND  pwr
S1  G$9:CATHODE  pas
S2  G$24:CATHODE  pas
T1  G$16:GND  pwr
T2  G$25:CATHODE  pas
U1  G$17:P$1  pas
U2  G$27:GND  pwr
V1  G$34:P$1  pas
V2  G$26:CATHODE  pas

## Footprint H807 (pad centres in mm)
One-wide female edge connector
drill 1.092 octagon: A1 4.763,28.575; A2 -1.587,28.575; B1 1.587,25.4; B2 -4.763,25.4; C1 4.763,22.225; C2 -1.587,22.225; D1 1.587,19.05; D2 -4.763,19.05; E1 4.763,15.875; E2 -1.587,15.875; F1 1.587,12.7; F2 -4.763,12.7; H1 4.763,9.525; H2 -1.587,9.525; J1 1.587,6.35; J2 -4.763,6.35; K1 4.763,3.175; K2 -1.587,3.175; L1 1.587,0; L2 -4.763,0; M1 4.763,-3.175; M2 -1.587,-3.175; N1 1.587,-6.35; N2 -4.763,-6.35; P1 4.763,-9.525; P2 -1.587,-9.525; R1 1.587,-12.7; R2 -4.763,-12.7; S1 4.763,-15.875; S2 -1.587,-15.875; T1 1.587,-19.05; T2 -4.763,-19.05; U1 4.763,-22.225; U2 -1.587,-22.225; V1 1.587,-25.4; V2 -4.763,-25.4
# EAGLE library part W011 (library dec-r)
One-sided 9 pin connector/cable with grounds (Negibus).

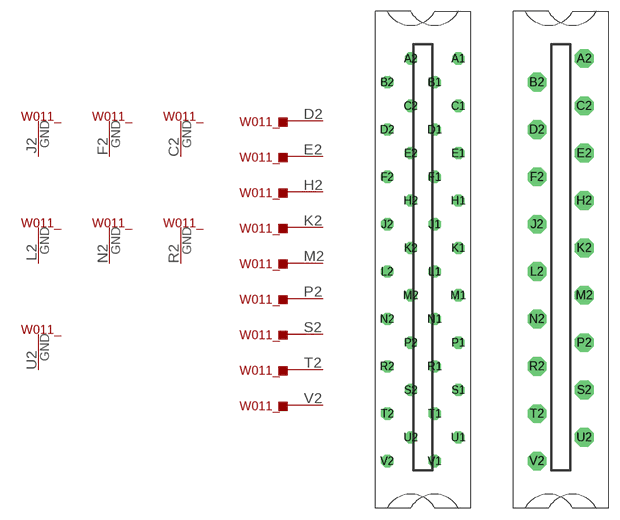
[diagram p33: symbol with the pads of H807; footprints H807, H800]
Designator prefix W011_; gates D=PIN E=PIN H=PIN K=PIN M=PIN P=PIN S=PIN T=PIN V=PIN G$1=T1GND G$2=T1GND G$3=T1GND G$6=T1GND G$8=T1GND G$10=T1GND G$12=T1GND

## W011  [H807]
C2  G$1:GND  pwr
D2  D:P$2
E2  E:P$2
F2  G$2:GND  pwr
H2  H:P$2
J2  G$3:GND  pwr
K2  K:P$2
L2  G$6:GND  pwr
M2  M:P$2
N2  G$8:GND  pwr
P2  P:P$2
R2  G$10:GND  pwr
S2  S:P$2
T2  T:P$2
U2  G$12:GND  pwr
V2  V:P$2

## W011O  [H800]
Pads as for H807

## W011S  [H807S]
Pads as for H807

## Footprint H807 (pad centres in mm)
One-wide female edge connector
drill 1.092 octagon: A1 4.763,28.575; A2 -1.587,28.575; B1 1.587,25.4; B2 -4.763,25.4; C1 4.763,22.225; C2 -1.587,22.225; D1 1.587,19.05; D2 -4.763,19.05; E1 4.763,15.875; E2 -1.587,15.875; F1 1.587,12.7; F2 -4.763,12.7; H1 4.763,9.525; H2 -1.587,9.525; J1 1.587,6.35; J2 -4.763,6.35; K1 4.763,3.175; K2 -1.587,3.175; L1 1.587,0; L2 -4.763,0; M1 4.763,-3.175; M2 -1.587,-3.175; N1 1.587,-6.35; N2 -4.763,-6.35; P1 4.763,-9.525; P2 -1.587,-9.525; R1 1.587,-12.7; R2 -4.763,-12.7; S1 4.763,-15.875; S2 -1.587,-15.875; T1 1.587,-19.05; T2 -4.763,-19.05; U1 4.763,-22.225; U2 -1.587,-22.225; V1 1.587,-25.4; V2 -4.763,-25.4

## Footprint H800 (pad centres in mm)
One-wide female edge connector, 18 pin
drill 1.676 octagon: A2 3.175,28.575; B2 -3.175,25.4; C2 3.175,22.225; D2 -3.175,19.05; E2 3.175,15.875; F2 -3.175,12.7; H2 3.175,9.525; J2 -3.175,6.35; K2 3.175,3.175; L2 -3.175,0; M2 3.175,-3.175; N2 -3.175,-6.35; P2 3.175,-9.525; R2 -3.175,-12.7; S2 3.175,-15.875; T2 -3.175,-19.05; U2 3.175,-22.225; V2 -3.175,-25.4

## Footprint H807S (pad centres in mm)
One-wide female edge connector, Side 2 only
drill 1.092 octagon: A2 -1.587,28.575; B2 -4.763,25.4; C2 -1.587,22.225; D2 -4.763,19.05; E2 -1.587,15.875; F2 -4.763,12.7; H2 -1.587,9.525; J2 -4.763,6.35; K2 -1.587,3.175; L2 -4.763,0; M2 -1.587,-3.175; N2 -4.763,-6.35; P2 -1.587,-9.525; R2 -4.763,-12.7; S2 -1.587,-15.875; T2 -4.763,-19.05; U2 -1.587,-22.225; V2 -4.763,-25.4
hole 1.092 at 4.763,28.575
hole 1.092 at 1.587,25.4
hole 1.092 at 4.763,22.225
hole 1.092 at 1.587,19.05
hole 1.092 at 4.763,15.875
hole 1.092 at 1.587,12.7
hole 1.092 at 4.763,9.525
hole 1.092 at 1.587,6.35
hole 1.092 at 4.763,3.175
hole 1.092 at 1.587,0
hole 1.092 at 4.763,-3.175
hole 1.092 at 1.587,-6.35
hole 1.092 at 4.763,-9.525
hole 1.092 at 1.587,-12.7
hole 1.092 at 4.763,-15.875
hole 1.092 at 1.587,-19.05
hole 1.092 at 4.763,-22.225
hole 1.092 at 1.587,-25.4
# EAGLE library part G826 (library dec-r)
Regulator and Power Detector

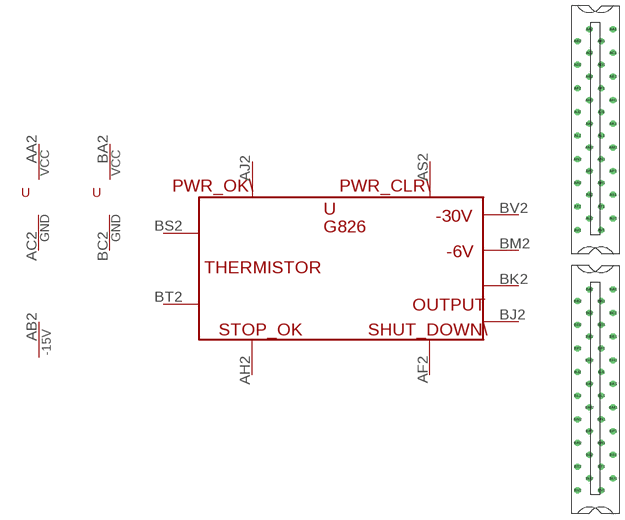
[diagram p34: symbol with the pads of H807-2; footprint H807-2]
Designator prefix -; gates G$1=G826 G$2=-15V G$3=POWER G$4=POWER

## G826  [H807-2]
AA2  G$3:VCC  pwr
AB2  G$2:-15V  pwr
AC2  G$3:GND  pwr
AF2  G$1:AF2  out
AH2  G$1:AH2  in
AJ2  G$1:AJ2
AS2  G$1:AS2
BA2  G$4:VCC  pwr
BC2  G$4:GND  pwr
BJ2  G$1:BJ2  out
BK2  G$1:BK2
BM2  G$1:-6V  sup
BS2  G$1:BS2  pas
BT2  G$1:BT2  pas
BV2  G$1:-30V  sup

## Footprint H807-2 (pad centres in mm)
Two-wide Female Edge Connector
drill 1.092 octagon: AA1 4.763,60.325; AA2 -1.587,60.325; AB1 1.587,57.15; AB2 -4.763,57.15; AC1 4.763,53.975; AC2 -1.587,53.975; AD1 1.587,50.8; AD2 -4.763,50.8; AE1 4.763,47.625; AE2 -1.587,47.625; AF1 1.587,44.45; AF2 -4.763,44.45; AH1 4.763,41.275; AH2 -1.587,41.275; AJ1 1.587,38.1; AJ2 -4.763,38.1; AK1 4.763,34.925; AK2 -1.587,34.925; AL1 1.587,31.75; AL2 -4.763,31.75; AM1 4.763,28.575; AM2 -1.587,28.575; AN1 1.587,25.4; AN2 -4.763,25.4; AP1 4.763,22.225; AP2 -1.587,22.225; AR1 1.587,19.05; AR2 -4.763,19.05; AS1 4.763,15.875; AS2 -1.587,15.875; AT1 1.587,12.7; AT2 -4.763,12.7; AU1 4.763,9.525; AU2 -1.587,9.525; AV1 1.587,6.35; AV2 -4.763,6.35; BA1 4.763,-9.525; BA2 -1.587,-9.525; BB1 1.587,-12.7; BB2 -4.763,-12.7; BC1 4.763,-15.875; BC2 -1.587,-15.875; BD1 1.587,-19.05; BD2 -4.763,-19.05; BE1 4.763,-22.225; BE2 -1.587,-22.225; BF1 1.587,-25.4; BF2 -4.763,-25.4; BH1 4.763,-28.575; BH2 -1.587,-28.575; BJ1 1.587,-31.75; BJ2 -4.763,-31.75; BK1 4.763,-34.925; BK2 -1.587,-34.925; BL1 1.587,-38.1; BL2 -4.763,-38.1; BM1 4.763,-41.275; BM2 -1.587,-41.275; BN1 1.587,-44.45; BN2 -4.763,-44.45; BP1 4.763,-47.625; BP2 -1.587,-47.625; BR1 1.587,-50.8; BR2 -4.763,-50.8; BS1 4.763,-53.975; BS2 -1.587,-53.975; BT1 1.587,-57.15; BT2 -4.763,-57.15; BU1 4.763,-60.325; BU2 -1.587,-60.325; BV1 1.587,-63.5; BV2 -4.763,-63.5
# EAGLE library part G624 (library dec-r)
Resistor Board

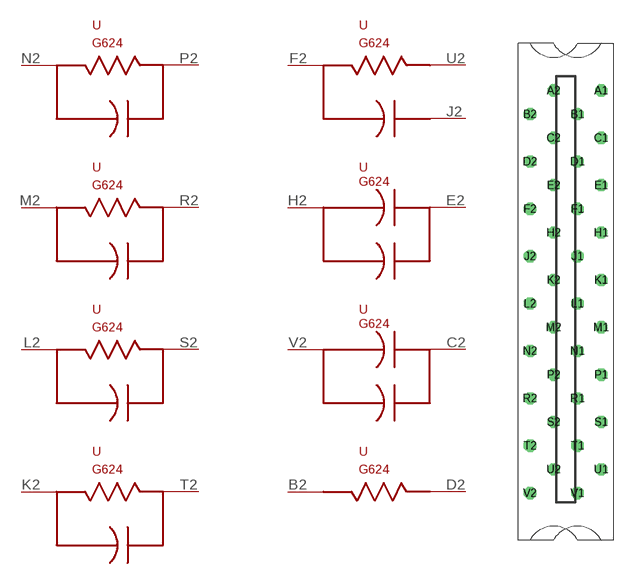
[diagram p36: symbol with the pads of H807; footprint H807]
Designator prefix -; gates G$1=G624A G$2=G624A G$3=G624A G$4=G624A G$5=G624B G$6=G624C G$7=G624C G$8=G624D

## G624  [H807]
B2  G$8:P$1  pas
C2  G$7:P$2  pas
D2  G$8:P$2  pas
E2  G$6:P$2  pas
F2  G$5:P$1  pas
H2  G$6:P$1  pas
J2  G$5:P$3  pas
K2  G$4:P$1  pas
L2  G$3:P$1  pas
M2  G$2:P$1  pas
N2  G$1:P$1  pas
P2  G$1:P$2  pas
R2  G$2:P$2  pas
S2  G$3:P$2  pas
T2  G$4:P$2  pas
U2  G$5:P$2  pas
V2  G$7:P$1  pas

## Footprint H807 (pad centres in mm)
One-wide female edge connector
drill 1.092 octagon: A1 4.763,28.575; A2 -1.587,28.575; B1 1.587,25.4; B2 -4.763,25.4; C1 4.763,22.225; C2 -1.587,22.225; D1 1.587,19.05; D2 -4.763,19.05; E1 4.763,15.875; E2 -1.587,15.875; F1 1.587,12.7; F2 -4.763,12.7; H1 4.763,9.525; H2 -1.587,9.525; J1 1.587,6.35; J2 -4.763,6.35; K1 4.763,3.175; K2 -1.587,3.175; L1 1.587,0; L2 -4.763,0; M1 4.763,-3.175; M2 -1.587,-3.175; N1 1.587,-6.35; N2 -4.763,-6.35; P1 4.763,-9.525; P2 -1.587,-9.525; R1 1.587,-12.7; R2 -4.763,-12.7; S1 4.763,-15.875; S2 -1.587,-15.875; T1 1.587,-19.05; T2 -4.763,-19.05; U1 4.763,-22.225; U2 -1.587,-22.225; V1 1.587,-25.4; V2 -4.763,-25.4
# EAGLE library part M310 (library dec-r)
Tapped Delay Line

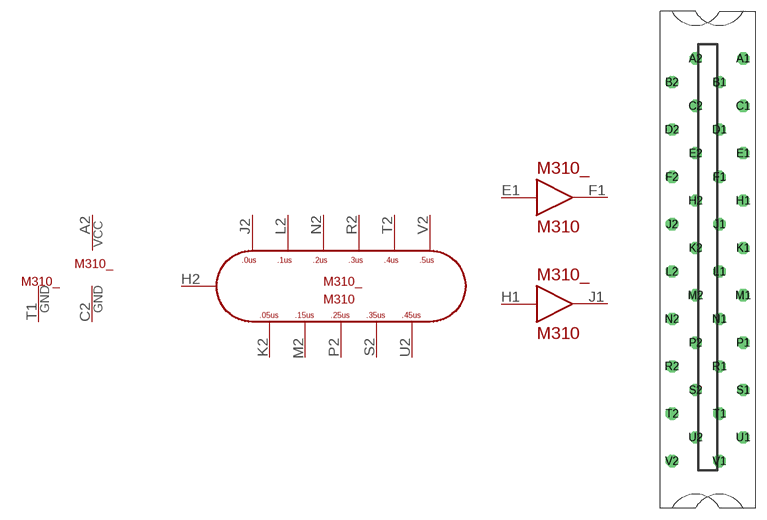
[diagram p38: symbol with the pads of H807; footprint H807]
Designator prefix M310_; gates G$1=M310 G$2=POWER G$3=T1GND G$4=BUFFER G$5=BUFFER

## M310  [H807]
A2  G$2:VCC  pwr
C2  G$2:GND  pwr
E1  G$4:IN  in
F1  G$4:OUT  out
H1  G$5:IN  in
H2  G$1:H2  in
J1  G$5:OUT  out
J2  G$1:J2  out
K2  G$1:K2  out
L2  G$1:L2  out
M2  G$1:M2  out
N2  G$1:N2  out
P2  G$1:P2  out
R2  G$1:R2  out
S2  G$1:S2  out
T1  G$3:GND  pwr
T2  G$1:T2  out
U2  G$1:U2  out
V2  G$1:V2  out

## Footprint H807 (pad centres in mm)
One-wide female edge connector
drill 1.092 octagon: A1 4.763,28.575; A2 -1.587,28.575; B1 1.587,25.4; B2 -4.763,25.4; C1 4.763,22.225; C2 -1.587,22.225; D1 1.587,19.05; D2 -4.763,19.05; E1 4.763,15.875; E2 -1.587,15.875; F1 1.587,12.7; F2 -4.763,12.7; H1 4.763,9.525; H2 -1.587,9.525; J1 1.587,6.35; J2 -4.763,6.35; K1 4.763,3.175; K2 -1.587,3.175; L1 1.587,0; L2 -4.763,0; M1 4.763,-3.175; M2 -1.587,-3.175; N1 1.587,-6.35; N2 -4.763,-6.35; P1 4.763,-9.525; P2 -1.587,-9.525; R1 1.587,-12.7; R2 -4.763,-12.7; S1 4.763,-15.875; S2 -1.587,-15.875; T1 1.587,-19.05; T2 -4.763,-19.05; U1 4.763,-22.225; U2 -1.587,-22.225; V1 1.587,-25.4; V2 -4.763,-25.4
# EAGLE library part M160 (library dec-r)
AND-NOR Gates

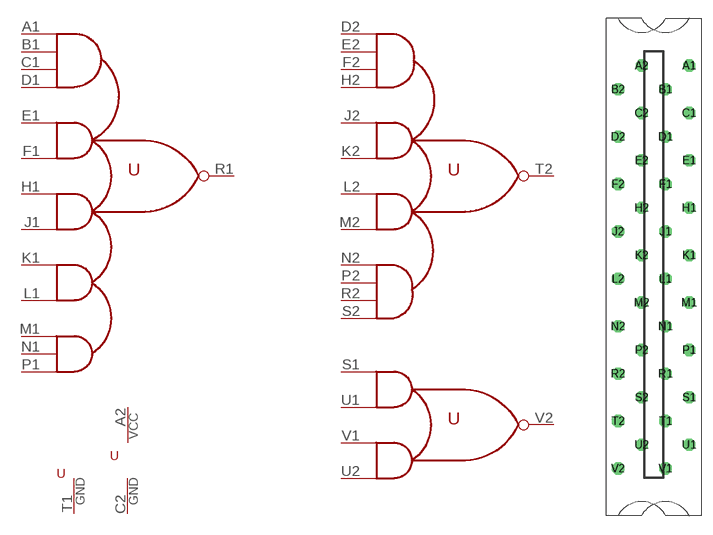
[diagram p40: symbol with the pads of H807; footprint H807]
Designator prefix -; gates G$3=AND-NOR G$4=POWER G$5=T1GND G$1=AND-NOR5 G$2=AND-NOR4

## M160  [H807]
A1  G$1:IN1A  in
A2  G$4:VCC  pwr
B1  G$1:IN1B  in
C1  G$1:IN1C  in
C2  G$4:GND  pwr
D1  G$1:IN1D  in
D2  G$2:IN1A  in
E1  G$1:IN2A  in
E2  G$2:IN1B  in
F1  G$1:IN2B  in
F2  G$2:IN1C  in
H1  G$1:IN3A  in
H2  G$2:IN1D  in
J1  G$1:IN3B  in
J2  G$2:IN2A  in
K1  G$1:IN4A  in
K2  G$2:IN2B  in
L1  G$1:IN4B  in
L2  G$2:IN3A  in
M1  G$1:IN5A  in
M2  G$2:IN3B  in
N1  G$1:IN5B  in
N2  G$2:IN4A  in
P1  G$1:IN5C  in
P2  G$2:IN4B  in
R1  G$1:OUT  out
R2  G$2:IN4C  in
S1  G$3:IN1A  in
S2  G$2:IN4D  in
T1  G$5:GND  pwr
T2  G$2:OUT  out
U1  G$3:IN1B  in
U2  G$3:IN2B  in
V1  G$3:IN2A  in
V2  G$3:OUT  out

## Footprint H807 (pad centres in mm)
One-wide female edge connector
drill 1.092 octagon: A1 4.763,28.575; A2 -1.587,28.575; B1 1.587,25.4; B2 -4.763,25.4; C1 4.763,22.225; C2 -1.587,22.225; D1 1.587,19.05; D2 -4.763,19.05; E1 4.763,15.875; E2 -1.587,15.875; F1 1.587,12.7; F2 -4.763,12.7; H1 4.763,9.525; H2 -1.587,9.525; J1 1.587,6.35; J2 -4.763,6.35; K1 4.763,3.175; K2 -1.587,3.175; L1 1.587,0; L2 -4.763,0; M1 4.763,-3.175; M2 -1.587,-3.175; N1 1.587,-6.35; N2 -4.763,-6.35; P1 4.763,-9.525; P2 -1.587,-9.525; R1 1.587,-12.7; R2 -4.763,-12.7; S1 4.763,-15.875; S2 -1.587,-15.875; T1 1.587,-19.05; T2 -4.763,-19.05; U1 4.763,-22.225; U2 -1.587,-22.225; V1 1.587,-25.4; V2 -4.763,-25.4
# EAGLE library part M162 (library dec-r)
Parity Circuit

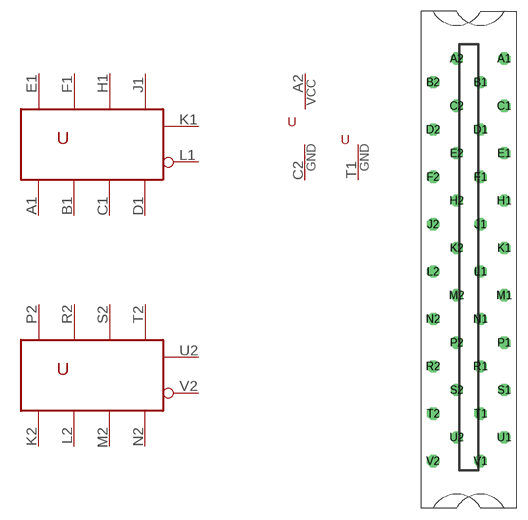
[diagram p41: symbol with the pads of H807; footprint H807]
Designator prefix -; gates G$1=M162 G$2=M162 G$3=POWER G$4=T1GND

## M162  [H807]
A1  G$1:1B  in
A2  G$3:VCC  pwr
B1  G$1:2B  in
C1  G$1:4B  in
C2  G$3:GND  pwr
D1  G$1:8B  in
E1  G$1:1A  in
F1  G$1:2A  in
H1  G$1:4A  in
J1  G$1:8A  in
K1  G$1:ODD  out
K2  G$2:1B  in
L1  G$1:EVEN  out
L2  G$2:2B  in
M2  G$2:4B  in
N2  G$2:8B  in
P2  G$2:1A  in
R2  G$2:2A  in
S2  G$2:4A  in
T1  G$4:GND  pwr
T2  G$2:8A  in
U2  G$2:ODD  out
V2  G$2:EVEN  out

## Footprint H807 (pad centres in mm)
One-wide female edge connector
drill 1.092 octagon: A1 4.763,28.575; A2 -1.587,28.575; B1 1.587,25.4; B2 -4.763,25.4; C1 4.763,22.225; C2 -1.587,22.225; D1 1.587,19.05; D2 -4.763,19.05; E1 4.763,15.875; E2 -1.587,15.875; F1 1.587,12.7; F2 -4.763,12.7; H1 4.763,9.525; H2 -1.587,9.525; J1 1.587,6.35; J2 -4.763,6.35; K1 4.763,3.175; K2 -1.587,3.175; L1 1.587,0; L2 -4.763,0; M1 4.763,-3.175; M2 -1.587,-3.175; N1 1.587,-6.35; N2 -4.763,-6.35; P1 4.763,-9.525; P2 -1.587,-9.525; R1 1.587,-12.7; R2 -4.763,-12.7; S1 4.763,-15.875; S2 -1.587,-15.875; T1 1.587,-19.05; T2 -4.763,-19.05; U1 4.763,-22.225; U2 -1.587,-22.225; V1 1.587,-25.4; V2 -4.763,-25.4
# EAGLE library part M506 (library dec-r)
Hex Negative Bus Receiver

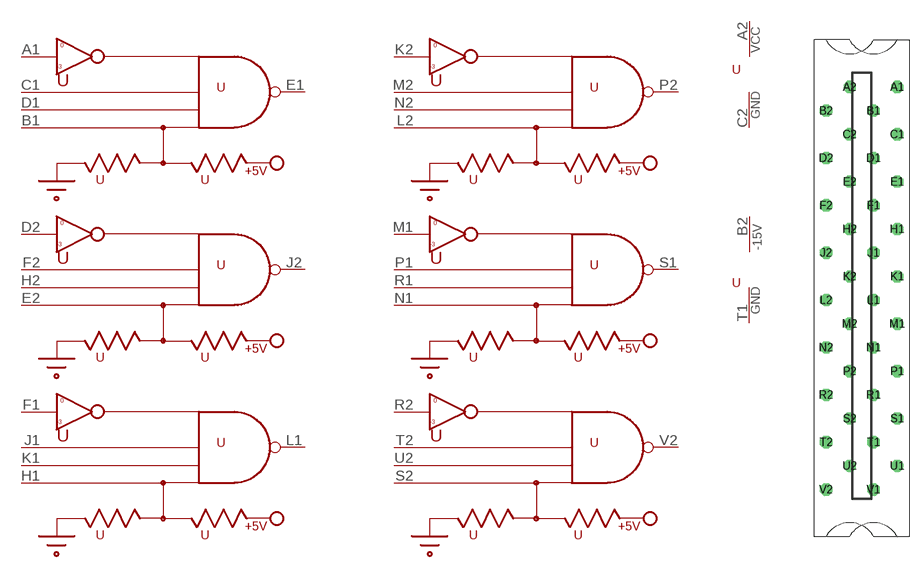
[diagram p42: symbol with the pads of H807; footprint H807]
Designator prefix -; gates G$1=M506 G$2=M506 G$3=M506 G$4=M506 G$5=M506 G$6=M506 G$7=POWER G$8=T1GND G$9=-15V

## M506  [H807]
A1  G$1:IN  in
A2  G$7:VCC  pwr
B1  G$1:IN2  in
B2  G$9:-15V  pwr
C1  G$1:IN3  in
C2  G$7:GND  pwr
D1  G$1:IN4  in
D2  G$2:IN  in
E1  G$1:OUT  out
E2  G$2:IN2  in
F1  G$3:IN  in
F2  G$2:IN3  in
H1  G$3:IN2  in
H2  G$2:IN4  in
J1  G$3:IN3  in
J2  G$2:OUT  out
K1  G$3:IN4  in
K2  G$4:IN  in
L1  G$3:OUT  out
L2  G$4:IN2  in
M1  G$5:IN  in
M2  G$4:IN3  in
N1  G$5:IN2  in
N2  G$4:IN4  in
P1  G$5:IN3  in
P2  G$4:OUT  out
R1  G$5:IN4  in
R2  G$6:IN  in
S1  G$5:OUT  out
S2  G$6:IN2  in
T1  G$8:GND  pwr
T2  G$6:IN3  in
U2  G$6:IN4  in
V2  G$6:OUT  out

## Footprint H807 (pad centres in mm)
One-wide female edge connector
drill 1.092 octagon: A1 4.763,28.575; A2 -1.587,28.575; B1 1.587,25.4; B2 -4.763,25.4; C1 4.763,22.225; C2 -1.587,22.225; D1 1.587,19.05; D2 -4.763,19.05; E1 4.763,15.875; E2 -1.587,15.875; F1 1.587,12.7; F2 -4.763,12.7; H1 4.763,9.525; H2 -1.587,9.525; J1 1.587,6.35; J2 -4.763,6.35; K1 4.763,3.175; K2 -1.587,3.175; L1 1.587,0; L2 -4.763,0; M1 4.763,-3.175; M2 -1.587,-3.175; N1 1.587,-6.35; N2 -4.763,-6.35; P1 4.763,-9.525; P2 -1.587,-9.525; R1 1.587,-12.7; R2 -4.763,-12.7; S1 4.763,-15.875; S2 -1.587,-15.875; T1 1.587,-19.05; T2 -4.763,-19.05; U1 4.763,-22.225; U2 -1.587,-22.225; V1 1.587,-25.4; V2 -4.763,-25.4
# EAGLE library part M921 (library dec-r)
Device Code Select Jumper Board

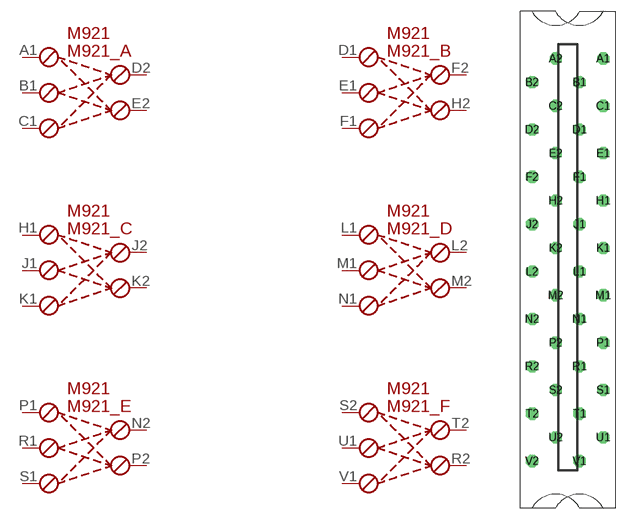
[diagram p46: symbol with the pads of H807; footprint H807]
Designator prefix M921_; gates A=M921 B=M921 C=M921 D=M921 E=M921 F=M921

## M921  [H807]
A1  A:L1
B1  A:L2
C1  A:L3
D1  B:L1
D2  A:R1
E1  B:L2
E2  A:R2
F1  B:L3
F2  B:R1
H1  C:L1
H2  B:R2
J1  C:L2
J2  C:R1
K1  C:L3
K2  C:R2
L1  D:L1
L2  D:R1
M1  D:L2
M2  D:R2
N1  D:L3
N2  E:R1
P1  E:L1
P2  E:R2
R1  E:L2
R2  F:R2
S1  E:L3
S2  F:L1
T2  F:R1
U1  F:L2
V1  F:L3

## Footprint H807 (pad centres in mm)
One-wide female edge connector
drill 1.092 octagon: A1 4.763,28.575; A2 -1.587,28.575; B1 1.587,25.4; B2 -4.763,25.4; C1 4.763,22.225; C2 -1.587,22.225; D1 1.587,19.05; D2 -4.763,19.05; E1 4.763,15.875; E2 -1.587,15.875; F1 1.587,12.7; F2 -4.763,12.7; H1 4.763,9.525; H2 -1.587,9.525; J1 1.587,6.35; J2 -4.763,6.35; K1 4.763,3.175; K2 -1.587,3.175; L1 1.587,0; L2 -4.763,0; M1 4.763,-3.175; M2 -1.587,-3.175; N1 1.587,-6.35; N2 -4.763,-6.35; P1 4.763,-9.525; P2 -1.587,-9.525; R1 1.587,-12.7; R2 -4.763,-12.7; S1 4.763,-15.875; S2 -1.587,-15.875; T1 1.587,-19.05; T2 -4.763,-19.05; U1 4.763,-22.225; U2 -1.587,-22.225; V1 1.587,-25.4; V2 -4.763,-25.4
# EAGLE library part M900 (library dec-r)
PDP-8/i Console Connector

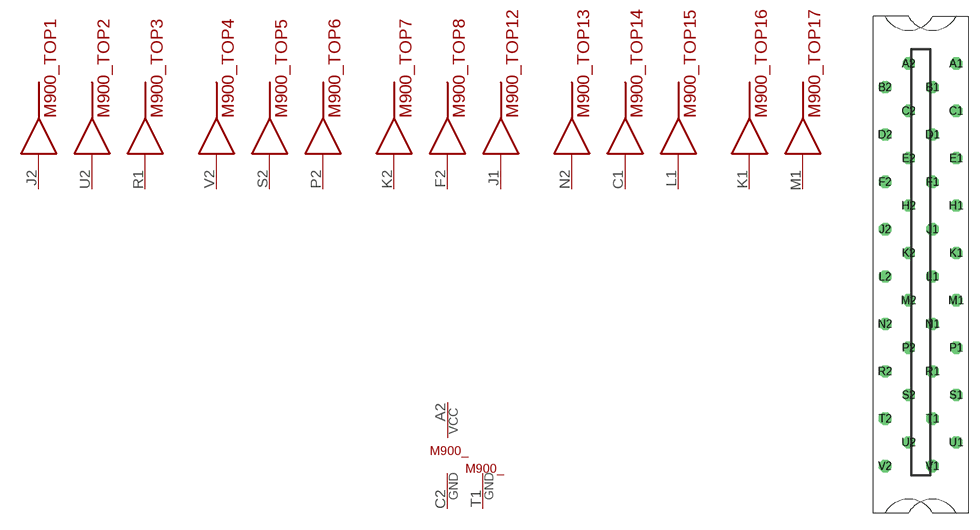
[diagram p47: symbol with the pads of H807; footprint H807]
Designator prefix M900_; gates G$31=T1GND G$32=POWER TOP1=M900 TOP2=M900 TOP3=M900 TOP4=M900 TOP5=M900 TOP6=M900 TOP7=M900 TOP8=M900 TOP12=M900 TOP13=M900 TOP14=M900 TOP15=M900 TOP16=M900 TOP17=M900 TOP18=M900 BOT1=M900 BOT2=M900 BOT3=M900 BOT4=M900 BOT5=M900 BOT6=M900 BOT9=M900 BOT11=M900 BOT12=M900 BOT14=M900 BOT15=M900 BOT16=M900 BOT17=M900 BOT18=M900 BOT19=M900

## M900  [H807]
A1  BOT17:1  in
A2  G$32:VCC  pwr
B1  BOT16:1  in
C1  TOP14:1  in
C2  G$32:GND  pwr
D1  BOT19:1  in
D2  BOT11:1  in
E1  BOT18:1  in
E2  BOT12:1  in
F1  TOP18:1  in
F2  TOP8:1  in
H1  BOT15:1  in
H2  BOT9:1  in
J1  TOP12:1  in
J2  TOP1:1  in
K1  TOP16:1  in
K2  TOP7:1  in
L1  TOP15:1  in
L2  BOT6:1  in
M1  TOP17:1  in
M2  BOT1:1  in
N1  BOT14:1  in
N2  TOP13:1  in
P1  BOT3:1  in
P2  TOP6:1  in
R1  TOP3:1  in
R2  BOT4:1  in
S1  BOT5:1  in
S2  TOP5:1  in
T1  G$31:GND  pwr
T2  BOT2:1  in
U2  TOP2:1  in
V2  TOP4:1  in

## Footprint H807 (pad centres in mm)
One-wide female edge connector
drill 1.092 octagon: A1 4.763,28.575; A2 -1.587,28.575; B1 1.587,25.4; B2 -4.763,25.4; C1 4.763,22.225; C2 -1.587,22.225; D1 1.587,19.05; D2 -4.763,19.05; E1 4.763,15.875; E2 -1.587,15.875; F1 1.587,12.7; F2 -4.763,12.7; H1 4.763,9.525; H2 -1.587,9.525; J1 1.587,6.35; J2 -4.763,6.35; K1 4.763,3.175; K2 -1.587,3.175; L1 1.587,0; L2 -4.763,0; M1 4.763,-3.175; M2 -1.587,-3.175; N1 1.587,-6.35; N2 -4.763,-6.35; P1 4.763,-9.525; P2 -1.587,-9.525; R1 1.587,-12.7; R2 -4.763,-12.7; S1 4.763,-15.875; S2 -1.587,-15.875; T1 1.587,-19.05; T2 -4.763,-19.05; U1 4.763,-22.225; U2 -1.587,-22.225; V1 1.587,-25.4; V2 -4.763,-25.4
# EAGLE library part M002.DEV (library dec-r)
15 Clamped Loads

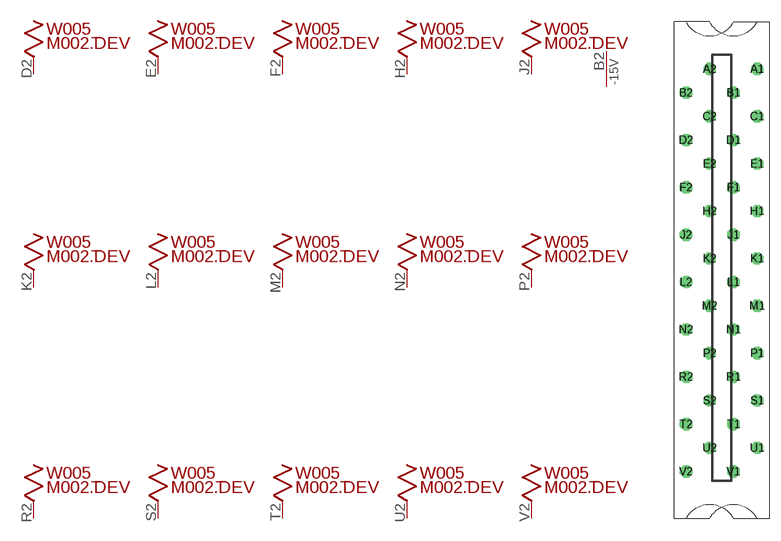
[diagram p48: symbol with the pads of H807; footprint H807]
Designator prefix W005_; gates G$1=W005A G$2=W005A G$3=W005A G$4=W005A G$5=W005A G$6=W005A G$7=W005A G$8=W005A G$9=W005A G$10=W005A G$11=W005A G$12=W005A G$13=W005A G$14=W005A G$15=W005A G$16=-15V G$17=T1GND

## M002.DEV  [H807]
B2  G$16:-15V  pwr
C2  G$17:GND  pwr
D2  G$1:P$1  pas
E2  G$2:P$1  pas
F2  G$3:P$1  pas
H2  G$4:P$1  pas
J2  G$5:P$1  pas
K2  G$6:P$1  pas
L2  G$7:P$1  pas
M2  G$8:P$1  pas
N2  G$9:P$1  pas
P2  G$10:P$1  pas
R2  G$11:P$1  pas
S2  G$12:P$1  pas
T2  G$13:P$1  pas
U2  G$14:P$1  pas
V2  G$15:P$1  pas

## Footprint H807 (pad centres in mm)
One-wide female edge connector
drill 1.092 octagon: A1 4.763,28.575; A2 -1.587,28.575; B1 1.587,25.4; B2 -4.763,25.4; C1 4.763,22.225; C2 -1.587,22.225; D1 1.587,19.05; D2 -4.763,19.05; E1 4.763,15.875; E2 -1.587,15.875; F1 1.587,12.7; F2 -4.763,12.7; H1 4.763,9.525; H2 -1.587,9.525; J1 1.587,6.35; J2 -4.763,6.35; K1 4.763,3.175; K2 -1.587,3.175; L1 1.587,0; L2 -4.763,0; M1 4.763,-3.175; M2 -1.587,-3.175; N1 1.587,-6.35; N2 -4.763,-6.35; P1 4.763,-9.525; P2 -1.587,-9.525; R1 1.587,-12.7; R2 -4.763,-12.7; S1 4.763,-15.875; S2 -1.587,-15.875; T1 1.587,-19.05; T2 -4.763,-19.05; U1 4.763,-22.225; U2 -1.587,-22.225; V1 1.587,-25.4; V2 -4.763,-25.4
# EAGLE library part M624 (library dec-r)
Bus Data Interface The M101 contains 15 two-input NAND gates. One input of each gate is tied to a common line so that all data signals can be enabled simultaneously. Each data signal presents one TTL load. The common input presents 15 loads. Each output can drive 10 loads. Power: 5V@82ma (max.)

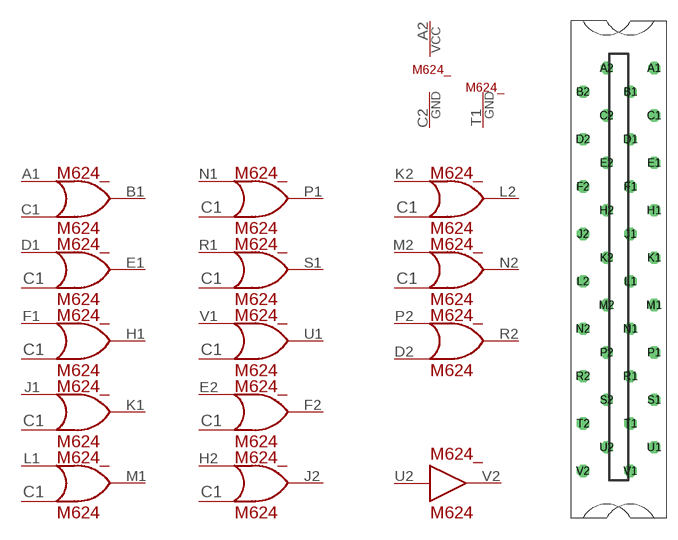
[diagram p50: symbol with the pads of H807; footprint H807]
Designator prefix M624_; gates G$16=POWER G$1=T1GND G$14=BUFFER G$17=OR2 G$2=OR1C G$9=OR1C G$10=OR1C G$11=OR1C G$4=OR1C G$5=OR1C G$6=OR1C G$7=OR1C G$8=OR1C G$3=OR1C G$12=OR1C G$13=OR2 G$18=OR1D

## M624  [H807]
A1  G$17:IN1  in
A2  G$16:VCC  pwr
B1  G$17:OUT  out
C1  G$17:IN2  in
C2  G$16:GND  pwr
D1  G$2:IN  in
D2  G$13:IN2  in
E1  G$2:OUT  out
E2  G$9:IN  in
F1  G$3:IN  in
F2  G$9:OUT  out
H1  G$3:OUT  out
H2  G$10:IN  in
J1  G$4:IN  in
J2  G$10:OUT  out
K1  G$4:OUT  out
K2  G$11:IN  in
L1  G$5:IN  in
L2  G$11:OUT  out
M1  G$5:OUT  out
M2  G$12:IN  in
N1  G$6:IN  in
N2  G$12:OUT  out
P1  G$6:OUT  out
P2  G$13:IN1  in
R1  G$7:IN  in
R2  G$13:OUT  out
S1  G$7:OUT  out
S2  G$18:IN  in
T1  G$1:GND  pwr
T2  G$18:OUT  out
U1  G$8:OUT  out
U2  G$14:IN  in
V1  G$8:IN  in
V2  G$14:OUT  out

## Footprint H807 (pad centres in mm)
One-wide female edge connector
drill 1.092 octagon: A1 4.763,28.575; A2 -1.587,28.575; B1 1.587,25.4; B2 -4.763,25.4; C1 4.763,22.225; C2 -1.587,22.225; D1 1.587,19.05; D2 -4.763,19.05; E1 4.763,15.875; E2 -1.587,15.875; F1 1.587,12.7; F2 -4.763,12.7; H1 4.763,9.525; H2 -1.587,9.525; J1 1.587,6.35; J2 -4.763,6.35; K1 4.763,3.175; K2 -1.587,3.175; L1 1.587,0; L2 -4.763,0; M1 4.763,-3.175; M2 -1.587,-3.175; N1 1.587,-6.35; N2 -4.763,-6.35; P1 4.763,-9.525; P2 -1.587,-9.525; R1 1.587,-12.7; R2 -4.763,-12.7; S1 4.763,-15.875; S2 -1.587,-15.875; T1 1.587,-19.05; T2 -4.763,-19.05; U1 4.763,-22.225; U2 -1.587,-22.225; V1 1.587,-25.4; V2 -4.763,-25.4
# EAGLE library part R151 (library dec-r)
Binary-to-Octal Decoder

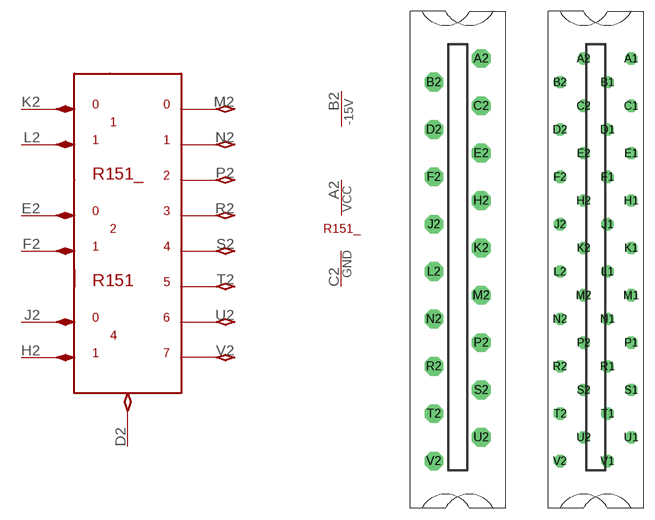
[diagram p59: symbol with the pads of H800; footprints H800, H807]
Designator prefix R151_; gates M=R151 G$2=-15V G$3=POWER

## R151O  [H800]
A2  G$3:VCC  pwr
B2  G$2:-15V  pwr
C2  G$3:GND  pwr
D2  M:D  in
E2  M:E  in
F2  M:F  in
H2  M:H  in
J2  M:J  in
K2  M:K  in
L2  M:L  in
M2  M:M  out
N2  M:N  out
P2  M:P  out
R2  M:R  out
S2  M:S  out
T2  M:T  out
U2  M:U  out
V2  M:V  out

## R151  [H807]
Pads as for H800

## R151S  [H807S]
Pads as for H800

## Footprint H800 (pad centres in mm)
One-wide female edge connector, 18 pin
drill 1.676 octagon: A2 3.175,28.575; B2 -3.175,25.4; C2 3.175,22.225; D2 -3.175,19.05; E2 3.175,15.875; F2 -3.175,12.7; H2 3.175,9.525; J2 -3.175,6.35; K2 3.175,3.175; L2 -3.175,0; M2 3.175,-3.175; N2 -3.175,-6.35; P2 3.175,-9.525; R2 -3.175,-12.7; S2 3.175,-15.875; T2 -3.175,-19.05; U2 3.175,-22.225; V2 -3.175,-25.4

## Footprint H807 (pad centres in mm)
One-wide female edge connector
drill 1.092 octagon: A1 4.763,28.575; A2 -1.587,28.575; B1 1.587,25.4; B2 -4.763,25.4; C1 4.763,22.225; C2 -1.587,22.225; D1 1.587,19.05; D2 -4.763,19.05; E1 4.763,15.875; E2 -1.587,15.875; F1 1.587,12.7; F2 -4.763,12.7; H1 4.763,9.525; H2 -1.587,9.525; J1 1.587,6.35; J2 -4.763,6.35; K1 4.763,3.175; K2 -1.587,3.175; L1 1.587,0; L2 -4.763,0; M1 4.763,-3.175; M2 -1.587,-3.175; N1 1.587,-6.35; N2 -4.763,-6.35; P1 4.763,-9.525; P2 -1.587,-9.525; R1 1.587,-12.7; R2 -4.763,-12.7; S1 4.763,-15.875; S2 -1.587,-15.875; T1 1.587,-19.05; T2 -4.763,-19.05; U1 4.763,-22.225; U2 -1.587,-22.225; V1 1.587,-25.4; V2 -4.763,-25.4

## Footprint H807S (pad centres in mm)
One-wide female edge connector, Side 2 only
drill 1.092 octagon: A2 -1.587,28.575; B2 -4.763,25.4; C2 -1.587,22.225; D2 -4.763,19.05; E2 -1.587,15.875; F2 -4.763,12.7; H2 -1.587,9.525; J2 -4.763,6.35; K2 -1.587,3.175; L2 -4.763,0; M2 -1.587,-3.175; N2 -4.763,-6.35; P2 -1.587,-9.525; R2 -4.763,-12.7; S2 -1.587,-15.875; T2 -4.763,-19.05; U2 -1.587,-22.225; V2 -4.763,-25.4
hole 1.092 at 4.763,28.575
hole 1.092 at 1.587,25.4
hole 1.092 at 4.763,22.225
hole 1.092 at 1.587,19.05
hole 1.092 at 4.763,15.875
hole 1.092 at 1.587,12.7
hole 1.092 at 4.763,9.525
hole 1.092 at 1.587,6.35
hole 1.092 at 4.763,3.175
hole 1.092 at 1.587,0
hole 1.092 at 4.763,-3.175
hole 1.092 at 1.587,-6.35
hole 1.092 at 4.763,-9.525
hole 1.092 at 1.587,-12.7
hole 1.092 at 4.763,-15.875
hole 1.092 at 1.587,-19.05
hole 1.092 at 4.763,-22.225
hole 1.092 at 1.587,-25.4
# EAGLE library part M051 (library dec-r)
M051 Positive Bus Converter

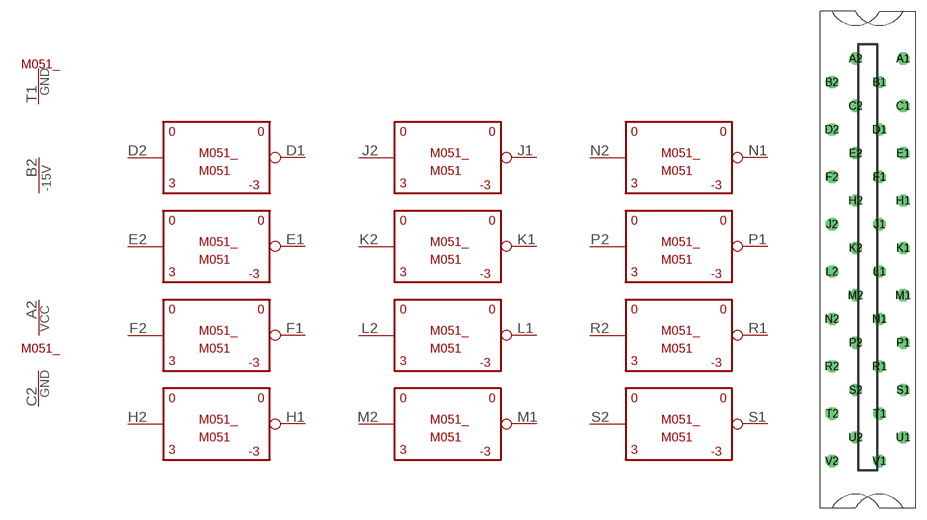
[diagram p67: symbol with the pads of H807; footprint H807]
Designator prefix M051_; gates G$8=POWER G$1=M051 G$2=M051 G$3=M051 G$4=M051 G$5=M051 G$6=M051 G$9=M051 G$10=M051 G$11=M051 G$12=M051 G$13=M051 G$14=M051 G$15=T1GND G$7=-15V

## M051  [H807]
A2  G$8:VCC  pwr
B2  G$7:-15V  pwr
C2  G$8:GND  pwr
D1  G$1:OUT  out
D2  G$1:IN  in
E1  G$2:OUT  out
E2  G$2:IN  in
F1  G$3:OUT  out
F2  G$3:IN  in
H1  G$4:OUT  out
H2  G$4:IN  in
J1  G$5:OUT  out
J2  G$5:IN  in
K1  G$6:OUT  out
K2  G$6:IN  in
L1  G$9:OUT  out
L2  G$9:IN  in
M1  G$10:OUT  out
M2  G$10:IN  in
N1  G$11:OUT  out
N2  G$11:IN  in
P1  G$12:OUT  out
P2  G$12:IN  in
R1  G$13:OUT  out
R2  G$13:IN  in
S1  G$14:OUT  out
S2  G$14:IN  in
T1  G$15:GND  pwr

## Footprint H807 (pad centres in mm)
One-wide female edge connector
drill 1.092 octagon: A1 4.763,28.575; A2 -1.587,28.575; B1 1.587,25.4; B2 -4.763,25.4; C1 4.763,22.225; C2 -1.587,22.225; D1 1.587,19.05; D2 -4.763,19.05; E1 4.763,15.875; E2 -1.587,15.875; F1 1.587,12.7; F2 -4.763,12.7; H1 4.763,9.525; H2 -1.587,9.525; J1 1.587,6.35; J2 -4.763,6.35; K1 4.763,3.175; K2 -1.587,3.175; L1 1.587,0; L2 -4.763,0; M1 4.763,-3.175; M2 -1.587,-3.175; N1 1.587,-6.35; N2 -4.763,-6.35; P1 4.763,-9.525; P2 -1.587,-9.525; R1 1.587,-12.7; R2 -4.763,-12.7; S1 4.763,-15.875; S2 -1.587,-15.875; T1 1.587,-19.05; T2 -4.763,-19.05; U1 4.763,-22.225; U2 -1.587,-22.225; V1 1.587,-25.4; V2 -4.763,-25.4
